VERSION 5.7 ;
  NOWIREEXTENSIONATPIN ON ;
  DIVIDERCHAR "/" ;
  BUSBITCHARS "[]" ;
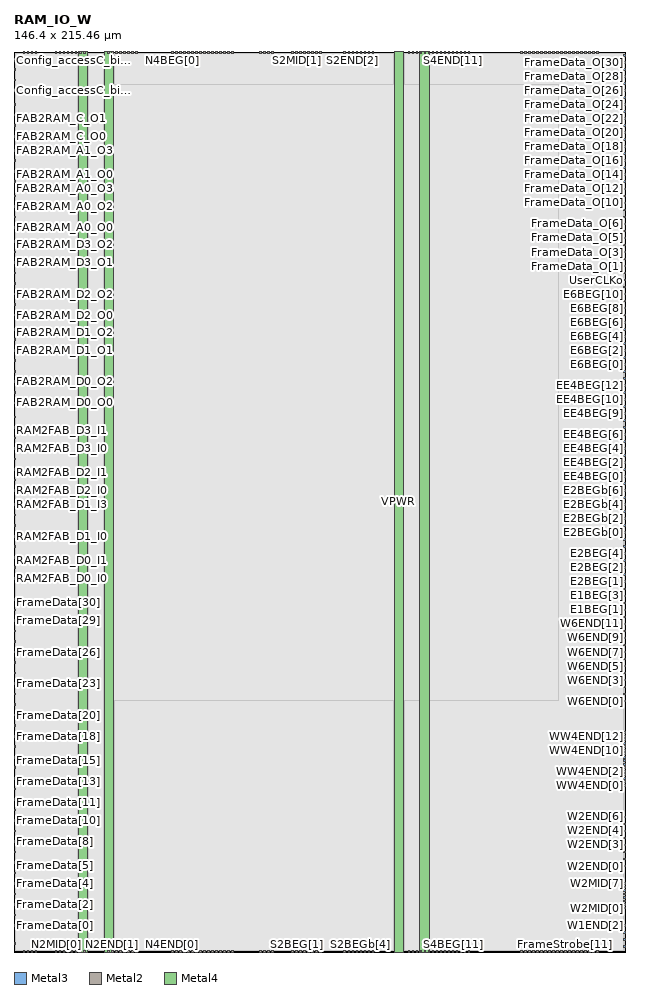
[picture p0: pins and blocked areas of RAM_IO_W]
MACRO RAM_IO_W
  CLASS BLOCK ;
  FOREIGN RAM_IO_W ;
  ORIGIN 0.000 0.000 ;
  SIZE 146.400 BY 215.460 ;
  PIN Config_accessC_bit0
    DIRECTION OUTPUT ;
    USE SIGNAL ;
    ANTENNADIFFAREA 2.647800 ;
    PORT
      LAYER Metal3 ;
        RECT 0.000 206.020 0.400 206.420 ;
    END
  END Config_accessC_bit0
  PIN Config_accessC_bit1
    DIRECTION OUTPUT ;
    USE SIGNAL ;
    ANTENNADIFFAREA 2.647800 ;
    PORT
      LAYER Metal3 ;
        RECT 0.000 208.540 0.400 208.940 ;
    END
  END Config_accessC_bit1
  PIN Config_accessC_bit2
    DIRECTION OUTPUT ;
    USE SIGNAL ;
    ANTENNADIFFAREA 2.647800 ;
    PORT
      LAYER Metal3 ;
        RECT 0.000 211.060 0.400 211.460 ;
    END
  END Config_accessC_bit2
  PIN Config_accessC_bit3
    DIRECTION OUTPUT ;
    USE SIGNAL ;
    ANTENNADIFFAREA 2.647800 ;
    PORT
      LAYER Metal3 ;
        RECT 0.000 213.580 0.400 213.980 ;
    END
  END Config_accessC_bit3
  PIN E1BEG[0]
    DIRECTION OUTPUT ;
    USE SIGNAL ;
    ANTENNADIFFAREA 2.724000 ;
    PORT
      LAYER Metal3 ;
        RECT 146.000 80.020 146.400 80.420 ;
    END
  END E1BEG[0]
  PIN E1BEG[1]
    DIRECTION OUTPUT ;
    USE SIGNAL ;
    ANTENNADIFFAREA 2.724000 ;
    PORT
      LAYER Metal3 ;
        RECT 146.000 81.700 146.400 82.100 ;
    END
  END E1BEG[1]
  PIN E1BEG[2]
    DIRECTION OUTPUT ;
    USE SIGNAL ;
    ANTENNADIFFAREA 2.724000 ;
    PORT
      LAYER Metal3 ;
        RECT 146.000 83.380 146.400 83.780 ;
    END
  END E1BEG[2]
  PIN E1BEG[3]
    DIRECTION OUTPUT ;
    USE SIGNAL ;
    ANTENNADIFFAREA 2.724000 ;
    PORT
      LAYER Metal3 ;
        RECT 146.000 85.060 146.400 85.460 ;
    END
  END E1BEG[3]
  PIN E2BEG[0]
    DIRECTION OUTPUT ;
    USE SIGNAL ;
    ANTENNADIFFAREA 2.724000 ;
    PORT
      LAYER Metal3 ;
        RECT 146.000 86.740 146.400 87.140 ;
    END
  END E2BEG[0]
  PIN E2BEG[1]
    DIRECTION OUTPUT ;
    USE SIGNAL ;
    ANTENNADIFFAREA 2.724000 ;
    PORT
      LAYER Metal3 ;
        RECT 146.000 88.420 146.400 88.820 ;
    END
  END E2BEG[1]
  PIN E2BEG[2]
    DIRECTION OUTPUT ;
    USE SIGNAL ;
    ANTENNADIFFAREA 2.724000 ;
    PORT
      LAYER Metal3 ;
        RECT 146.000 90.100 146.400 90.500 ;
    END
  END E2BEG[2]
  PIN E2BEG[3]
    DIRECTION OUTPUT ;
    USE SIGNAL ;
    ANTENNADIFFAREA 2.724000 ;
    PORT
      LAYER Metal3 ;
        RECT 146.000 91.780 146.400 92.180 ;
    END
  END E2BEG[3]
  PIN E2BEG[4]
    DIRECTION OUTPUT ;
    USE SIGNAL ;
    ANTENNADIFFAREA 2.724000 ;
    PORT
      LAYER Metal3 ;
        RECT 146.000 93.460 146.400 93.860 ;
    END
  END E2BEG[4]
  PIN E2BEG[5]
    DIRECTION OUTPUT ;
    USE SIGNAL ;
    ANTENNADIFFAREA 2.724000 ;
    PORT
      LAYER Metal3 ;
        RECT 146.000 95.140 146.400 95.540 ;
    END
  END E2BEG[5]
  PIN E2BEG[6]
    DIRECTION OUTPUT ;
    USE SIGNAL ;
    ANTENNADIFFAREA 2.724000 ;
    PORT
      LAYER Metal3 ;
        RECT 146.000 96.820 146.400 97.220 ;
    END
  END E2BEG[6]
  PIN E2BEG[7]
    DIRECTION OUTPUT ;
    USE SIGNAL ;
    ANTENNADIFFAREA 2.724000 ;
    PORT
      LAYER Metal3 ;
        RECT 146.000 98.500 146.400 98.900 ;
    END
  END E2BEG[7]
  PIN E2BEGb[0]
    DIRECTION OUTPUT ;
    USE SIGNAL ;
    ANTENNADIFFAREA 2.724000 ;
    PORT
      LAYER Metal3 ;
        RECT 146.000 100.180 146.400 100.580 ;
    END
  END E2BEGb[0]
  PIN E2BEGb[1]
    DIRECTION OUTPUT ;
    USE SIGNAL ;
    ANTENNADIFFAREA 2.724000 ;
    PORT
      LAYER Metal3 ;
        RECT 146.000 101.860 146.400 102.260 ;
    END
  END E2BEGb[1]
  PIN E2BEGb[2]
    DIRECTION OUTPUT ;
    USE SIGNAL ;
    ANTENNADIFFAREA 2.724000 ;
    PORT
      LAYER Metal3 ;
        RECT 146.000 103.540 146.400 103.940 ;
    END
  END E2BEGb[2]
  PIN E2BEGb[3]
    DIRECTION OUTPUT ;
    USE SIGNAL ;
    ANTENNADIFFAREA 2.724000 ;
    PORT
      LAYER Metal3 ;
        RECT 146.000 105.220 146.400 105.620 ;
    END
  END E2BEGb[3]
  PIN E2BEGb[4]
    DIRECTION OUTPUT ;
    USE SIGNAL ;
    ANTENNADIFFAREA 2.724000 ;
    PORT
      LAYER Metal3 ;
        RECT 146.000 106.900 146.400 107.300 ;
    END
  END E2BEGb[4]
  PIN E2BEGb[5]
    DIRECTION OUTPUT ;
    USE SIGNAL ;
    ANTENNADIFFAREA 2.724000 ;
    PORT
      LAYER Metal3 ;
        RECT 146.000 108.580 146.400 108.980 ;
    END
  END E2BEGb[5]
  PIN E2BEGb[6]
    DIRECTION OUTPUT ;
    USE SIGNAL ;
    ANTENNADIFFAREA 2.724000 ;
    PORT
      LAYER Metal3 ;
        RECT 146.000 110.260 146.400 110.660 ;
    END
  END E2BEGb[6]
  PIN E2BEGb[7]
    DIRECTION OUTPUT ;
    USE SIGNAL ;
    ANTENNADIFFAREA 2.724000 ;
    PORT
      LAYER Metal3 ;
        RECT 146.000 111.940 146.400 112.340 ;
    END
  END E2BEGb[7]
  PIN E6BEG[0]
    DIRECTION OUTPUT ;
    USE SIGNAL ;
    ANTENNADIFFAREA 2.724000 ;
    PORT
      LAYER Metal3 ;
        RECT 146.000 140.500 146.400 140.900 ;
    END
  END E6BEG[0]
  PIN E6BEG[10]
    DIRECTION OUTPUT ;
    USE SIGNAL ;
    ANTENNADIFFAREA 2.724000 ;
    PORT
      LAYER Metal3 ;
        RECT 146.000 157.300 146.400 157.700 ;
    END
  END E6BEG[10]
  PIN E6BEG[11]
    DIRECTION OUTPUT ;
    USE SIGNAL ;
    ANTENNADIFFAREA 2.724000 ;
    PORT
      LAYER Metal3 ;
        RECT 146.000 158.980 146.400 159.380 ;
    END
  END E6BEG[11]
  PIN E6BEG[1]
    DIRECTION OUTPUT ;
    USE SIGNAL ;
    ANTENNADIFFAREA 2.724000 ;
    PORT
      LAYER Metal3 ;
        RECT 146.000 142.180 146.400 142.580 ;
    END
  END E6BEG[1]
  PIN E6BEG[2]
    DIRECTION OUTPUT ;
    USE SIGNAL ;
    ANTENNADIFFAREA 2.724000 ;
    PORT
      LAYER Metal3 ;
        RECT 146.000 143.860 146.400 144.260 ;
    END
  END E6BEG[2]
  PIN E6BEG[3]
    DIRECTION OUTPUT ;
    USE SIGNAL ;
    ANTENNADIFFAREA 2.724000 ;
    PORT
      LAYER Metal3 ;
        RECT 146.000 145.540 146.400 145.940 ;
    END
  END E6BEG[3]
  PIN E6BEG[4]
    DIRECTION OUTPUT ;
    USE SIGNAL ;
    ANTENNADIFFAREA 2.724000 ;
    PORT
      LAYER Metal3 ;
        RECT 146.000 147.220 146.400 147.620 ;
    END
  END E6BEG[4]
  PIN E6BEG[5]
    DIRECTION OUTPUT ;
    USE SIGNAL ;
    ANTENNADIFFAREA 2.724000 ;
    PORT
      LAYER Metal3 ;
        RECT 146.000 148.900 146.400 149.300 ;
    END
  END E6BEG[5]
  PIN E6BEG[6]
    DIRECTION OUTPUT ;
    USE SIGNAL ;
    ANTENNADIFFAREA 2.724000 ;
    PORT
      LAYER Metal3 ;
        RECT 146.000 150.580 146.400 150.980 ;
    END
  END E6BEG[6]
  PIN E6BEG[7]
    DIRECTION OUTPUT ;
    USE SIGNAL ;
    ANTENNADIFFAREA 2.724000 ;
    PORT
      LAYER Metal3 ;
        RECT 146.000 152.260 146.400 152.660 ;
    END
  END E6BEG[7]
  PIN E6BEG[8]
    DIRECTION OUTPUT ;
    USE SIGNAL ;
    ANTENNADIFFAREA 2.724000 ;
    PORT
      LAYER Metal3 ;
        RECT 146.000 153.940 146.400 154.340 ;
    END
  END E6BEG[8]
  PIN E6BEG[9]
    DIRECTION OUTPUT ;
    USE SIGNAL ;
    ANTENNADIFFAREA 2.724000 ;
    PORT
      LAYER Metal3 ;
        RECT 146.000 155.620 146.400 156.020 ;
    END
  END E6BEG[9]
  PIN EE4BEG[0]
    DIRECTION OUTPUT ;
    USE SIGNAL ;
    ANTENNADIFFAREA 2.724000 ;
    PORT
      LAYER Metal3 ;
        RECT 146.000 113.620 146.400 114.020 ;
    END
  END EE4BEG[0]
  PIN EE4BEG[10]
    DIRECTION OUTPUT ;
    USE SIGNAL ;
    ANTENNADIFFAREA 2.724000 ;
    PORT
      LAYER Metal3 ;
        RECT 146.000 130.420 146.400 130.820 ;
    END
  END EE4BEG[10]
  PIN EE4BEG[11]
    DIRECTION OUTPUT ;
    USE SIGNAL ;
    ANTENNADIFFAREA 2.724000 ;
    PORT
      LAYER Metal3 ;
        RECT 146.000 132.100 146.400 132.500 ;
    END
  END EE4BEG[11]
  PIN EE4BEG[12]
    DIRECTION OUTPUT ;
    USE SIGNAL ;
    ANTENNADIFFAREA 2.724000 ;
    PORT
      LAYER Metal3 ;
        RECT 146.000 133.780 146.400 134.180 ;
    END
  END EE4BEG[12]
  PIN EE4BEG[13]
    DIRECTION OUTPUT ;
    USE SIGNAL ;
    ANTENNADIFFAREA 2.724000 ;
    PORT
      LAYER Metal3 ;
        RECT 146.000 135.460 146.400 135.860 ;
    END
  END EE4BEG[13]
  PIN EE4BEG[14]
    DIRECTION OUTPUT ;
    USE SIGNAL ;
    ANTENNADIFFAREA 2.724000 ;
    PORT
      LAYER Metal3 ;
        RECT 146.000 137.140 146.400 137.540 ;
    END
  END EE4BEG[14]
  PIN EE4BEG[15]
    DIRECTION OUTPUT ;
    USE SIGNAL ;
    ANTENNADIFFAREA 2.724000 ;
    PORT
      LAYER Metal3 ;
        RECT 146.000 138.820 146.400 139.220 ;
    END
  END EE4BEG[15]
  PIN EE4BEG[1]
    DIRECTION OUTPUT ;
    USE SIGNAL ;
    ANTENNADIFFAREA 2.724000 ;
    PORT
      LAYER Metal3 ;
        RECT 146.000 115.300 146.400 115.700 ;
    END
  END EE4BEG[1]
  PIN EE4BEG[2]
    DIRECTION OUTPUT ;
    USE SIGNAL ;
    ANTENNADIFFAREA 2.724000 ;
    PORT
      LAYER Metal3 ;
        RECT 146.000 116.980 146.400 117.380 ;
    END
  END EE4BEG[2]
  PIN EE4BEG[3]
    DIRECTION OUTPUT ;
    USE SIGNAL ;
    ANTENNADIFFAREA 2.724000 ;
    PORT
      LAYER Metal3 ;
        RECT 146.000 118.660 146.400 119.060 ;
    END
  END EE4BEG[3]
  PIN EE4BEG[4]
    DIRECTION OUTPUT ;
    USE SIGNAL ;
    ANTENNADIFFAREA 2.724000 ;
    PORT
      LAYER Metal3 ;
        RECT 146.000 120.340 146.400 120.740 ;
    END
  END EE4BEG[4]
  PIN EE4BEG[5]
    DIRECTION OUTPUT ;
    USE SIGNAL ;
    ANTENNADIFFAREA 2.724000 ;
    PORT
      LAYER Metal3 ;
        RECT 146.000 122.020 146.400 122.420 ;
    END
  END EE4BEG[5]
  PIN EE4BEG[6]
    DIRECTION OUTPUT ;
    USE SIGNAL ;
    ANTENNADIFFAREA 2.724000 ;
    PORT
      LAYER Metal3 ;
        RECT 146.000 123.700 146.400 124.100 ;
    END
  END EE4BEG[6]
  PIN EE4BEG[7]
    DIRECTION OUTPUT ;
    USE SIGNAL ;
    ANTENNADIFFAREA 2.724000 ;
    PORT
      LAYER Metal3 ;
        RECT 146.000 125.380 146.400 125.780 ;
    END
  END EE4BEG[7]
  PIN EE4BEG[8]
    DIRECTION OUTPUT ;
    USE SIGNAL ;
    ANTENNADIFFAREA 2.724000 ;
    PORT
      LAYER Metal3 ;
        RECT 146.000 127.060 146.400 127.460 ;
    END
  END EE4BEG[8]
  PIN EE4BEG[9]
    DIRECTION OUTPUT ;
    USE SIGNAL ;
    ANTENNADIFFAREA 2.724000 ;
    PORT
      LAYER Metal3 ;
        RECT 146.000 128.740 146.400 129.140 ;
    END
  END EE4BEG[9]
  PIN FAB2RAM_A0_O0
    DIRECTION OUTPUT ;
    USE SIGNAL ;
    ANTENNADIFFAREA 3.023500 ;
    PORT
      LAYER Metal3 ;
        RECT 0.000 173.260 0.400 173.660 ;
    END
  END FAB2RAM_A0_O0
  PIN FAB2RAM_A0_O1
    DIRECTION OUTPUT ;
    USE SIGNAL ;
    ANTENNADIFFAREA 3.023500 ;
    PORT
      LAYER Metal3 ;
        RECT 0.000 175.780 0.400 176.180 ;
    END
  END FAB2RAM_A0_O1
  PIN FAB2RAM_A0_O2
    DIRECTION OUTPUT ;
    USE SIGNAL ;
    ANTENNADIFFAREA 3.023500 ;
    PORT
      LAYER Metal3 ;
        RECT 0.000 178.300 0.400 178.700 ;
    END
  END FAB2RAM_A0_O2
  PIN FAB2RAM_A0_O3
    DIRECTION OUTPUT ;
    USE SIGNAL ;
    ANTENNADIFFAREA 3.023500 ;
    PORT
      LAYER Metal3 ;
        RECT 0.000 180.820 0.400 181.220 ;
    END
  END FAB2RAM_A0_O3
  PIN FAB2RAM_A1_O0
    DIRECTION OUTPUT ;
    USE SIGNAL ;
    ANTENNADIFFAREA 3.023500 ;
    PORT
      LAYER Metal3 ;
        RECT 0.000 184.180 0.400 184.580 ;
    END
  END FAB2RAM_A1_O0
  PIN FAB2RAM_A1_O1
    DIRECTION OUTPUT ;
    USE SIGNAL ;
    ANTENNADIFFAREA 3.023500 ;
    PORT
      LAYER Metal3 ;
        RECT 0.000 186.700 0.400 187.100 ;
    END
  END FAB2RAM_A1_O1
  PIN FAB2RAM_A1_O2
    DIRECTION OUTPUT ;
    USE SIGNAL ;
    ANTENNADIFFAREA 3.023500 ;
    PORT
      LAYER Metal3 ;
        RECT 0.000 189.220 0.400 189.620 ;
    END
  END FAB2RAM_A1_O2
  PIN FAB2RAM_A1_O3
    DIRECTION OUTPUT ;
    USE SIGNAL ;
    ANTENNADIFFAREA 3.023500 ;
    PORT
      LAYER Metal3 ;
        RECT 0.000 191.740 0.400 192.140 ;
    END
  END FAB2RAM_A1_O3
  PIN FAB2RAM_C_O0
    DIRECTION OUTPUT ;
    USE SIGNAL ;
    ANTENNADIFFAREA 3.023500 ;
    PORT
      LAYER Metal3 ;
        RECT 0.000 195.100 0.400 195.500 ;
    END
  END FAB2RAM_C_O0
  PIN FAB2RAM_C_O1
    DIRECTION OUTPUT ;
    USE SIGNAL ;
    ANTENNADIFFAREA 3.023500 ;
    PORT
      LAYER Metal3 ;
        RECT 0.000 197.620 0.400 198.020 ;
    END
  END FAB2RAM_C_O1
  PIN FAB2RAM_C_O2
    DIRECTION OUTPUT ;
    USE SIGNAL ;
    ANTENNADIFFAREA 3.023500 ;
    PORT
      LAYER Metal3 ;
        RECT 0.000 200.140 0.400 200.540 ;
    END
  END FAB2RAM_C_O2
  PIN FAB2RAM_C_O3
    DIRECTION OUTPUT ;
    USE SIGNAL ;
    ANTENNADIFFAREA 3.023500 ;
    PORT
      LAYER Metal3 ;
        RECT 0.000 202.660 0.400 203.060 ;
    END
  END FAB2RAM_C_O3
  PIN FAB2RAM_D0_O0
    DIRECTION OUTPUT ;
    USE SIGNAL ;
    ANTENNADIFFAREA 3.023500 ;
    PORT
      LAYER Metal3 ;
        RECT 0.000 131.260 0.400 131.660 ;
    END
  END FAB2RAM_D0_O0
  PIN FAB2RAM_D0_O1
    DIRECTION OUTPUT ;
    USE SIGNAL ;
    ANTENNADIFFAREA 3.023500 ;
    PORT
      LAYER Metal3 ;
        RECT 0.000 133.780 0.400 134.180 ;
    END
  END FAB2RAM_D0_O1
  PIN FAB2RAM_D0_O2
    DIRECTION OUTPUT ;
    USE SIGNAL ;
    ANTENNADIFFAREA 3.023500 ;
    PORT
      LAYER Metal3 ;
        RECT 0.000 136.300 0.400 136.700 ;
    END
  END FAB2RAM_D0_O2
  PIN FAB2RAM_D0_O3
    DIRECTION OUTPUT ;
    USE SIGNAL ;
    ANTENNADIFFAREA 3.023500 ;
    PORT
      LAYER Metal3 ;
        RECT 0.000 138.820 0.400 139.220 ;
    END
  END FAB2RAM_D0_O3
  PIN FAB2RAM_D1_O0
    DIRECTION OUTPUT ;
    USE SIGNAL ;
    ANTENNADIFFAREA 3.023500 ;
    PORT
      LAYER Metal3 ;
        RECT 0.000 141.340 0.400 141.740 ;
    END
  END FAB2RAM_D1_O0
  PIN FAB2RAM_D1_O1
    DIRECTION OUTPUT ;
    USE SIGNAL ;
    ANTENNADIFFAREA 3.023500 ;
    PORT
      LAYER Metal3 ;
        RECT 0.000 143.860 0.400 144.260 ;
    END
  END FAB2RAM_D1_O1
  PIN FAB2RAM_D1_O2
    DIRECTION OUTPUT ;
    USE SIGNAL ;
    ANTENNADIFFAREA 3.023500 ;
    PORT
      LAYER Metal3 ;
        RECT 0.000 146.380 0.400 146.780 ;
    END
  END FAB2RAM_D1_O2
  PIN FAB2RAM_D1_O3
    DIRECTION OUTPUT ;
    USE SIGNAL ;
    ANTENNADIFFAREA 3.023500 ;
    PORT
      LAYER Metal3 ;
        RECT 0.000 148.900 0.400 149.300 ;
    END
  END FAB2RAM_D1_O3
  PIN FAB2RAM_D2_O0
    DIRECTION OUTPUT ;
    USE SIGNAL ;
    ANTENNADIFFAREA 3.023500 ;
    PORT
      LAYER Metal3 ;
        RECT 0.000 152.260 0.400 152.660 ;
    END
  END FAB2RAM_D2_O0
  PIN FAB2RAM_D2_O1
    DIRECTION OUTPUT ;
    USE SIGNAL ;
    ANTENNADIFFAREA 3.023500 ;
    PORT
      LAYER Metal3 ;
        RECT 0.000 154.780 0.400 155.180 ;
    END
  END FAB2RAM_D2_O1
  PIN FAB2RAM_D2_O2
    DIRECTION OUTPUT ;
    USE SIGNAL ;
    ANTENNADIFFAREA 3.023500 ;
    PORT
      LAYER Metal3 ;
        RECT 0.000 157.300 0.400 157.700 ;
    END
  END FAB2RAM_D2_O2
  PIN FAB2RAM_D2_O3
    DIRECTION OUTPUT ;
    USE SIGNAL ;
    ANTENNADIFFAREA 3.023500 ;
    PORT
      LAYER Metal3 ;
        RECT 0.000 159.820 0.400 160.220 ;
    END
  END FAB2RAM_D2_O3
  PIN FAB2RAM_D3_O0
    DIRECTION OUTPUT ;
    USE SIGNAL ;
    ANTENNADIFFAREA 3.023500 ;
    PORT
      LAYER Metal3 ;
        RECT 0.000 162.340 0.400 162.740 ;
    END
  END FAB2RAM_D3_O0
  PIN FAB2RAM_D3_O1
    DIRECTION OUTPUT ;
    USE SIGNAL ;
    ANTENNADIFFAREA 3.023500 ;
    PORT
      LAYER Metal3 ;
        RECT 0.000 164.860 0.400 165.260 ;
    END
  END FAB2RAM_D3_O1
  PIN FAB2RAM_D3_O2
    DIRECTION OUTPUT ;
    USE SIGNAL ;
    ANTENNADIFFAREA 3.023500 ;
    PORT
      LAYER Metal3 ;
        RECT 0.000 167.380 0.400 167.780 ;
    END
  END FAB2RAM_D3_O2
  PIN FAB2RAM_D3_O3
    DIRECTION OUTPUT ;
    USE SIGNAL ;
    ANTENNADIFFAREA 3.023500 ;
    PORT
      LAYER Metal3 ;
        RECT 0.000 169.900 0.400 170.300 ;
    END
  END FAB2RAM_D3_O3
  PIN FrameData[0]
    DIRECTION INPUT ;
    USE SIGNAL ;
    ANTENNAGATEAREA 1.987700 ;
    ANTENNADIFFAREA 22.169399 ;
    PORT
      LAYER Metal3 ;
        RECT 0.000 6.100 0.400 6.500 ;
    END
  END FrameData[0]
  PIN FrameData[10]
    DIRECTION INPUT ;
    USE SIGNAL ;
    ANTENNAGATEAREA 1.987700 ;
    ANTENNADIFFAREA 22.169399 ;
    PORT
      LAYER Metal3 ;
        RECT 0.000 31.300 0.400 31.700 ;
    END
  END FrameData[10]
  PIN FrameData[11]
    DIRECTION INPUT ;
    USE SIGNAL ;
    ANTENNAGATEAREA 1.987700 ;
    ANTENNADIFFAREA 22.169399 ;
    PORT
      LAYER Metal3 ;
        RECT 0.000 33.820 0.400 34.220 ;
    END
  END FrameData[11]
  PIN FrameData[12]
    DIRECTION INPUT ;
    USE SIGNAL ;
    ANTENNAGATEAREA 1.987700 ;
    ANTENNADIFFAREA 22.169399 ;
    PORT
      LAYER Metal3 ;
        RECT 0.000 36.340 0.400 36.740 ;
    END
  END FrameData[12]
  PIN FrameData[13]
    DIRECTION INPUT ;
    USE SIGNAL ;
    ANTENNAGATEAREA 1.987700 ;
    ANTENNADIFFAREA 22.169399 ;
    PORT
      LAYER Metal3 ;
        RECT 0.000 38.860 0.400 39.260 ;
    END
  END FrameData[13]
  PIN FrameData[14]
    DIRECTION INPUT ;
    USE SIGNAL ;
    ANTENNAGATEAREA 1.987700 ;
    ANTENNADIFFAREA 22.169399 ;
    PORT
      LAYER Metal3 ;
        RECT 0.000 41.380 0.400 41.780 ;
    END
  END FrameData[14]
  PIN FrameData[15]
    DIRECTION INPUT ;
    USE SIGNAL ;
    ANTENNAGATEAREA 1.987700 ;
    ANTENNADIFFAREA 22.169399 ;
    PORT
      LAYER Metal3 ;
        RECT 0.000 43.900 0.400 44.300 ;
    END
  END FrameData[15]
  PIN FrameData[16]
    DIRECTION INPUT ;
    USE SIGNAL ;
    ANTENNAGATEAREA 1.987700 ;
    ANTENNADIFFAREA 22.169399 ;
    PORT
      LAYER Metal3 ;
        RECT 0.000 46.420 0.400 46.820 ;
    END
  END FrameData[16]
  PIN FrameData[17]
    DIRECTION INPUT ;
    USE SIGNAL ;
    ANTENNAGATEAREA 1.987700 ;
    ANTENNADIFFAREA 22.169399 ;
    PORT
      LAYER Metal3 ;
        RECT 0.000 48.940 0.400 49.340 ;
    END
  END FrameData[17]
  PIN FrameData[18]
    DIRECTION INPUT ;
    USE SIGNAL ;
    ANTENNAGATEAREA 1.987700 ;
    ANTENNADIFFAREA 22.169399 ;
    PORT
      LAYER Metal3 ;
        RECT 0.000 51.460 0.400 51.860 ;
    END
  END FrameData[18]
  PIN FrameData[19]
    DIRECTION INPUT ;
    USE SIGNAL ;
    ANTENNAGATEAREA 1.987700 ;
    ANTENNADIFFAREA 22.169399 ;
    PORT
      LAYER Metal3 ;
        RECT 0.000 53.980 0.400 54.380 ;
    END
  END FrameData[19]
  PIN FrameData[1]
    DIRECTION INPUT ;
    USE SIGNAL ;
    ANTENNAGATEAREA 1.987700 ;
    ANTENNADIFFAREA 22.169399 ;
    PORT
      LAYER Metal3 ;
        RECT 0.000 8.620 0.400 9.020 ;
    END
  END FrameData[1]
  PIN FrameData[20]
    DIRECTION INPUT ;
    USE SIGNAL ;
    ANTENNAGATEAREA 1.987700 ;
    ANTENNADIFFAREA 22.169399 ;
    PORT
      LAYER Metal3 ;
        RECT 0.000 56.500 0.400 56.900 ;
    END
  END FrameData[20]
  PIN FrameData[21]
    DIRECTION INPUT ;
    USE SIGNAL ;
    ANTENNAGATEAREA 1.987700 ;
    ANTENNADIFFAREA 22.169399 ;
    PORT
      LAYER Metal3 ;
        RECT 0.000 59.020 0.400 59.420 ;
    END
  END FrameData[21]
  PIN FrameData[22]
    DIRECTION INPUT ;
    USE SIGNAL ;
    ANTENNAGATEAREA 1.987700 ;
    ANTENNADIFFAREA 22.169399 ;
    PORT
      LAYER Metal3 ;
        RECT 0.000 61.540 0.400 61.940 ;
    END
  END FrameData[22]
  PIN FrameData[23]
    DIRECTION INPUT ;
    USE SIGNAL ;
    ANTENNAGATEAREA 1.987700 ;
    ANTENNADIFFAREA 22.169399 ;
    PORT
      LAYER Metal3 ;
        RECT 0.000 64.060 0.400 64.460 ;
    END
  END FrameData[23]
  PIN FrameData[24]
    DIRECTION INPUT ;
    USE SIGNAL ;
    ANTENNAGATEAREA 2.168400 ;
    ANTENNADIFFAREA 24.184799 ;
    PORT
      LAYER Metal3 ;
        RECT 0.000 66.580 0.400 66.980 ;
    END
  END FrameData[24]
  PIN FrameData[25]
    DIRECTION INPUT ;
    USE SIGNAL ;
    ANTENNAGATEAREA 2.168400 ;
    ANTENNADIFFAREA 24.184799 ;
    PORT
      LAYER Metal3 ;
        RECT 0.000 69.100 0.400 69.500 ;
    END
  END FrameData[25]
  PIN FrameData[26]
    DIRECTION INPUT ;
    USE SIGNAL ;
    ANTENNAGATEAREA 2.168400 ;
    ANTENNADIFFAREA 24.184799 ;
    PORT
      LAYER Metal3 ;
        RECT 0.000 71.620 0.400 72.020 ;
    END
  END FrameData[26]
  PIN FrameData[27]
    DIRECTION INPUT ;
    USE SIGNAL ;
    ANTENNAGATEAREA 2.168400 ;
    ANTENNADIFFAREA 24.184799 ;
    PORT
      LAYER Metal3 ;
        RECT 0.000 74.140 0.400 74.540 ;
    END
  END FrameData[27]
  PIN FrameData[28]
    DIRECTION INPUT ;
    USE SIGNAL ;
    ANTENNAGATEAREA 2.168400 ;
    ANTENNADIFFAREA 24.184799 ;
    PORT
      LAYER Metal3 ;
        RECT 0.000 76.660 0.400 77.060 ;
    END
  END FrameData[28]
  PIN FrameData[29]
    DIRECTION INPUT ;
    USE SIGNAL ;
    ANTENNAGATEAREA 2.168400 ;
    ANTENNADIFFAREA 24.184799 ;
    PORT
      LAYER Metal3 ;
        RECT 0.000 79.180 0.400 79.580 ;
    END
  END FrameData[29]
  PIN FrameData[2]
    DIRECTION INPUT ;
    USE SIGNAL ;
    ANTENNAGATEAREA 1.987700 ;
    ANTENNADIFFAREA 22.169399 ;
    PORT
      LAYER Metal3 ;
        RECT 0.000 11.140 0.400 11.540 ;
    END
  END FrameData[2]
  PIN FrameData[30]
    DIRECTION INPUT ;
    USE SIGNAL ;
    ANTENNAGATEAREA 2.168400 ;
    ANTENNADIFFAREA 24.184799 ;
    PORT
      LAYER Metal3 ;
        RECT 0.000 81.700 0.400 82.100 ;
    END
  END FrameData[30]
  PIN FrameData[31]
    DIRECTION INPUT ;
    USE SIGNAL ;
    ANTENNAGATEAREA 2.168400 ;
    ANTENNADIFFAREA 24.184799 ;
    PORT
      LAYER Metal3 ;
        RECT 0.000 84.220 0.400 84.620 ;
    END
  END FrameData[31]
  PIN FrameData[3]
    DIRECTION INPUT ;
    USE SIGNAL ;
    ANTENNAGATEAREA 1.987700 ;
    ANTENNADIFFAREA 22.169399 ;
    PORT
      LAYER Metal3 ;
        RECT 0.000 13.660 0.400 14.060 ;
    END
  END FrameData[3]
  PIN FrameData[4]
    DIRECTION INPUT ;
    USE SIGNAL ;
    ANTENNAGATEAREA 1.987700 ;
    ANTENNADIFFAREA 22.169399 ;
    PORT
      LAYER Metal3 ;
        RECT 0.000 16.180 0.400 16.580 ;
    END
  END FrameData[4]
  PIN FrameData[5]
    DIRECTION INPUT ;
    USE SIGNAL ;
    ANTENNAGATEAREA 1.987700 ;
    ANTENNADIFFAREA 22.169399 ;
    PORT
      LAYER Metal3 ;
        RECT 0.000 18.700 0.400 19.100 ;
    END
  END FrameData[5]
  PIN FrameData[6]
    DIRECTION INPUT ;
    USE SIGNAL ;
    ANTENNAGATEAREA 1.987700 ;
    ANTENNADIFFAREA 22.169399 ;
    PORT
      LAYER Metal3 ;
        RECT 0.000 21.220 0.400 21.620 ;
    END
  END FrameData[6]
  PIN FrameData[7]
    DIRECTION INPUT ;
    USE SIGNAL ;
    ANTENNAGATEAREA 1.987700 ;
    ANTENNADIFFAREA 22.169399 ;
    PORT
      LAYER Metal3 ;
        RECT 0.000 23.740 0.400 24.140 ;
    END
  END FrameData[7]
  PIN FrameData[8]
    DIRECTION INPUT ;
    USE SIGNAL ;
    ANTENNAGATEAREA 1.987700 ;
    ANTENNADIFFAREA 22.169399 ;
    PORT
      LAYER Metal3 ;
        RECT 0.000 26.260 0.400 26.660 ;
    END
  END FrameData[8]
  PIN FrameData[9]
    DIRECTION INPUT ;
    USE SIGNAL ;
    ANTENNAGATEAREA 1.987700 ;
    ANTENNADIFFAREA 22.169399 ;
    PORT
      LAYER Metal3 ;
        RECT 0.000 28.780 0.400 29.180 ;
    END
  END FrameData[9]
  PIN FrameData_O[0]
    DIRECTION OUTPUT ;
    USE SIGNAL ;
    ANTENNADIFFAREA 2.724000 ;
    PORT
      LAYER Metal3 ;
        RECT 146.000 162.340 146.400 162.740 ;
    END
  END FrameData_O[0]
  PIN FrameData_O[10]
    DIRECTION OUTPUT ;
    USE SIGNAL ;
    ANTENNADIFFAREA 2.724000 ;
    PORT
      LAYER Metal3 ;
        RECT 146.000 179.140 146.400 179.540 ;
    END
  END FrameData_O[10]
  PIN FrameData_O[11]
    DIRECTION OUTPUT ;
    USE SIGNAL ;
    ANTENNADIFFAREA 2.724000 ;
    PORT
      LAYER Metal3 ;
        RECT 146.000 180.820 146.400 181.220 ;
    END
  END FrameData_O[11]
  PIN FrameData_O[12]
    DIRECTION OUTPUT ;
    USE SIGNAL ;
    ANTENNADIFFAREA 2.724000 ;
    PORT
      LAYER Metal3 ;
        RECT 146.000 182.500 146.400 182.900 ;
    END
  END FrameData_O[12]
  PIN FrameData_O[13]
    DIRECTION OUTPUT ;
    USE SIGNAL ;
    ANTENNADIFFAREA 2.724000 ;
    PORT
      LAYER Metal3 ;
        RECT 146.000 184.180 146.400 184.580 ;
    END
  END FrameData_O[13]
  PIN FrameData_O[14]
    DIRECTION OUTPUT ;
    USE SIGNAL ;
    ANTENNADIFFAREA 2.724000 ;
    PORT
      LAYER Metal3 ;
        RECT 146.000 185.860 146.400 186.260 ;
    END
  END FrameData_O[14]
  PIN FrameData_O[15]
    DIRECTION OUTPUT ;
    USE SIGNAL ;
    ANTENNADIFFAREA 2.724000 ;
    PORT
      LAYER Metal3 ;
        RECT 146.000 187.540 146.400 187.940 ;
    END
  END FrameData_O[15]
  PIN FrameData_O[16]
    DIRECTION OUTPUT ;
    USE SIGNAL ;
    ANTENNADIFFAREA 2.724000 ;
    PORT
      LAYER Metal3 ;
        RECT 146.000 189.220 146.400 189.620 ;
    END
  END FrameData_O[16]
  PIN FrameData_O[17]
    DIRECTION OUTPUT ;
    USE SIGNAL ;
    ANTENNADIFFAREA 2.724000 ;
    PORT
      LAYER Metal3 ;
        RECT 146.000 190.900 146.400 191.300 ;
    END
  END FrameData_O[17]
  PIN FrameData_O[18]
    DIRECTION OUTPUT ;
    USE SIGNAL ;
    ANTENNADIFFAREA 2.724000 ;
    PORT
      LAYER Metal3 ;
        RECT 146.000 192.580 146.400 192.980 ;
    END
  END FrameData_O[18]
  PIN FrameData_O[19]
    DIRECTION OUTPUT ;
    USE SIGNAL ;
    ANTENNADIFFAREA 2.724000 ;
    PORT
      LAYER Metal3 ;
        RECT 146.000 194.260 146.400 194.660 ;
    END
  END FrameData_O[19]
  PIN FrameData_O[1]
    DIRECTION OUTPUT ;
    USE SIGNAL ;
    ANTENNADIFFAREA 2.724000 ;
    PORT
      LAYER Metal3 ;
        RECT 146.000 164.020 146.400 164.420 ;
    END
  END FrameData_O[1]
  PIN FrameData_O[20]
    DIRECTION OUTPUT ;
    USE SIGNAL ;
    ANTENNADIFFAREA 2.724000 ;
    PORT
      LAYER Metal3 ;
        RECT 146.000 195.940 146.400 196.340 ;
    END
  END FrameData_O[20]
  PIN FrameData_O[21]
    DIRECTION OUTPUT ;
    USE SIGNAL ;
    ANTENNADIFFAREA 2.724000 ;
    PORT
      LAYER Metal3 ;
        RECT 146.000 197.620 146.400 198.020 ;
    END
  END FrameData_O[21]
  PIN FrameData_O[22]
    DIRECTION OUTPUT ;
    USE SIGNAL ;
    ANTENNADIFFAREA 2.724000 ;
    PORT
      LAYER Metal3 ;
        RECT 146.000 199.300 146.400 199.700 ;
    END
  END FrameData_O[22]
  PIN FrameData_O[23]
    DIRECTION OUTPUT ;
    USE SIGNAL ;
    ANTENNADIFFAREA 2.724000 ;
    PORT
      LAYER Metal3 ;
        RECT 146.000 200.980 146.400 201.380 ;
    END
  END FrameData_O[23]
  PIN FrameData_O[24]
    DIRECTION OUTPUT ;
    USE SIGNAL ;
    ANTENNADIFFAREA 2.724000 ;
    PORT
      LAYER Metal3 ;
        RECT 146.000 202.660 146.400 203.060 ;
    END
  END FrameData_O[24]
  PIN FrameData_O[25]
    DIRECTION OUTPUT ;
    USE SIGNAL ;
    ANTENNADIFFAREA 2.724000 ;
    PORT
      LAYER Metal3 ;
        RECT 146.000 204.340 146.400 204.740 ;
    END
  END FrameData_O[25]
  PIN FrameData_O[26]
    DIRECTION OUTPUT ;
    USE SIGNAL ;
    ANTENNADIFFAREA 2.724000 ;
    PORT
      LAYER Metal3 ;
        RECT 146.000 206.020 146.400 206.420 ;
    END
  END FrameData_O[26]
  PIN FrameData_O[27]
    DIRECTION OUTPUT ;
    USE SIGNAL ;
    ANTENNADIFFAREA 2.724000 ;
    PORT
      LAYER Metal3 ;
        RECT 146.000 207.700 146.400 208.100 ;
    END
  END FrameData_O[27]
  PIN FrameData_O[28]
    DIRECTION OUTPUT ;
    USE SIGNAL ;
    ANTENNADIFFAREA 2.724000 ;
    PORT
      LAYER Metal3 ;
        RECT 146.000 209.380 146.400 209.780 ;
    END
  END FrameData_O[28]
  PIN FrameData_O[29]
    DIRECTION OUTPUT ;
    USE SIGNAL ;
    ANTENNADIFFAREA 2.724000 ;
    PORT
      LAYER Metal3 ;
        RECT 146.000 211.060 146.400 211.460 ;
    END
  END FrameData_O[29]
  PIN FrameData_O[2]
    DIRECTION OUTPUT ;
    USE SIGNAL ;
    ANTENNADIFFAREA 2.724000 ;
    PORT
      LAYER Metal3 ;
        RECT 146.000 165.700 146.400 166.100 ;
    END
  END FrameData_O[2]
  PIN FrameData_O[30]
    DIRECTION OUTPUT ;
    USE SIGNAL ;
    ANTENNADIFFAREA 2.724000 ;
    PORT
      LAYER Metal3 ;
        RECT 146.000 212.740 146.400 213.140 ;
    END
  END FrameData_O[30]
  PIN FrameData_O[31]
    DIRECTION OUTPUT ;
    USE SIGNAL ;
    ANTENNADIFFAREA 2.724000 ;
    PORT
      LAYER Metal3 ;
        RECT 146.000 214.420 146.400 214.820 ;
    END
  END FrameData_O[31]
  PIN FrameData_O[3]
    DIRECTION OUTPUT ;
    USE SIGNAL ;
    ANTENNADIFFAREA 2.724000 ;
    PORT
      LAYER Metal3 ;
        RECT 146.000 167.380 146.400 167.780 ;
    END
  END FrameData_O[3]
  PIN FrameData_O[4]
    DIRECTION OUTPUT ;
    USE SIGNAL ;
    ANTENNADIFFAREA 2.724000 ;
    PORT
      LAYER Metal3 ;
        RECT 146.000 169.060 146.400 169.460 ;
    END
  END FrameData_O[4]
  PIN FrameData_O[5]
    DIRECTION OUTPUT ;
    USE SIGNAL ;
    ANTENNADIFFAREA 2.724000 ;
    PORT
      LAYER Metal3 ;
        RECT 146.000 170.740 146.400 171.140 ;
    END
  END FrameData_O[5]
  PIN FrameData_O[6]
    DIRECTION OUTPUT ;
    USE SIGNAL ;
    ANTENNADIFFAREA 2.724000 ;
    PORT
      LAYER Metal3 ;
        RECT 146.000 172.420 146.400 172.820 ;
    END
  END FrameData_O[6]
  PIN FrameData_O[7]
    DIRECTION OUTPUT ;
    USE SIGNAL ;
    ANTENNADIFFAREA 2.724000 ;
    PORT
      LAYER Metal3 ;
        RECT 146.000 174.100 146.400 174.500 ;
    END
  END FrameData_O[7]
  PIN FrameData_O[8]
    DIRECTION OUTPUT ;
    USE SIGNAL ;
    ANTENNADIFFAREA 2.724000 ;
    PORT
      LAYER Metal3 ;
        RECT 146.000 175.780 146.400 176.180 ;
    END
  END FrameData_O[8]
  PIN FrameData_O[9]
    DIRECTION OUTPUT ;
    USE SIGNAL ;
    ANTENNADIFFAREA 2.724000 ;
    PORT
      LAYER Metal3 ;
        RECT 146.000 177.460 146.400 177.860 ;
    END
  END FrameData_O[9]
  PIN FrameStrobe[0]
    DIRECTION INPUT ;
    USE SIGNAL ;
    ANTENNAGATEAREA 6.753500 ;
    ANTENNADIFFAREA 66.508202 ;
    PORT
      LAYER Metal2 ;
        RECT 121.240 0.000 121.640 0.400 ;
    END
  END FrameStrobe[0]
  PIN FrameStrobe[10]
    DIRECTION INPUT ;
    USE SIGNAL ;
    ANTENNAGATEAREA 1.823900 ;
    ANTENNADIFFAREA 18.138599 ;
    PORT
      LAYER Metal2 ;
        RECT 130.840 0.000 131.240 0.400 ;
    END
  END FrameStrobe[10]
  PIN FrameStrobe[11]
    DIRECTION INPUT ;
    USE SIGNAL ;
    ANTENNAGATEAREA 0.180700 ;
    ANTENNADIFFAREA 2.015400 ;
    PORT
      LAYER Metal2 ;
        RECT 131.800 0.000 132.200 0.400 ;
    END
  END FrameStrobe[11]
  PIN FrameStrobe[12]
    DIRECTION INPUT ;
    USE SIGNAL ;
    ANTENNAGATEAREA 0.180700 ;
    ANTENNADIFFAREA 2.015400 ;
    PORT
      LAYER Metal2 ;
        RECT 132.760 0.000 133.160 0.400 ;
    END
  END FrameStrobe[12]
  PIN FrameStrobe[13]
    DIRECTION INPUT ;
    USE SIGNAL ;
    ANTENNAGATEAREA 0.180700 ;
    ANTENNADIFFAREA 2.015400 ;
    PORT
      LAYER Metal2 ;
        RECT 133.720 0.000 134.120 0.400 ;
    END
  END FrameStrobe[13]
  PIN FrameStrobe[14]
    DIRECTION INPUT ;
    USE SIGNAL ;
    ANTENNAGATEAREA 0.180700 ;
    ANTENNADIFFAREA 2.015400 ;
    PORT
      LAYER Metal2 ;
        RECT 134.680 0.000 135.080 0.400 ;
    END
  END FrameStrobe[14]
  PIN FrameStrobe[15]
    DIRECTION INPUT ;
    USE SIGNAL ;
    ANTENNAGATEAREA 0.180700 ;
    ANTENNADIFFAREA 2.015400 ;
    PORT
      LAYER Metal2 ;
        RECT 135.640 0.000 136.040 0.400 ;
    END
  END FrameStrobe[15]
  PIN FrameStrobe[16]
    DIRECTION INPUT ;
    USE SIGNAL ;
    ANTENNAGATEAREA 0.180700 ;
    ANTENNADIFFAREA 2.015400 ;
    PORT
      LAYER Metal2 ;
        RECT 136.600 0.000 137.000 0.400 ;
    END
  END FrameStrobe[16]
  PIN FrameStrobe[17]
    DIRECTION INPUT ;
    USE SIGNAL ;
    ANTENNAGATEAREA 0.180700 ;
    ANTENNADIFFAREA 2.015400 ;
    PORT
      LAYER Metal2 ;
        RECT 137.560 0.000 137.960 0.400 ;
    END
  END FrameStrobe[17]
  PIN FrameStrobe[18]
    DIRECTION INPUT ;
    USE SIGNAL ;
    ANTENNAGATEAREA 0.180700 ;
    ANTENNADIFFAREA 2.015400 ;
    PORT
      LAYER Metal2 ;
        RECT 138.520 0.000 138.920 0.400 ;
    END
  END FrameStrobe[18]
  PIN FrameStrobe[19]
    DIRECTION INPUT ;
    USE SIGNAL ;
    ANTENNAGATEAREA 0.180700 ;
    ANTENNADIFFAREA 2.015400 ;
    PORT
      LAYER Metal2 ;
        RECT 139.480 0.000 139.880 0.400 ;
    END
  END FrameStrobe[19]
  PIN FrameStrobe[1]
    DIRECTION INPUT ;
    USE SIGNAL ;
    ANTENNAGATEAREA 6.753500 ;
    ANTENNADIFFAREA 66.508202 ;
    PORT
      LAYER Metal2 ;
        RECT 122.200 0.000 122.600 0.400 ;
    END
  END FrameStrobe[1]
  PIN FrameStrobe[2]
    DIRECTION INPUT ;
    USE SIGNAL ;
    ANTENNAGATEAREA 6.753500 ;
    ANTENNADIFFAREA 66.508202 ;
    PORT
      LAYER Metal2 ;
        RECT 123.160 0.000 123.560 0.400 ;
    END
  END FrameStrobe[2]
  PIN FrameStrobe[3]
    DIRECTION INPUT ;
    USE SIGNAL ;
    ANTENNAGATEAREA 6.753500 ;
    ANTENNADIFFAREA 66.508202 ;
    PORT
      LAYER Metal2 ;
        RECT 124.120 0.000 124.520 0.400 ;
    END
  END FrameStrobe[3]
  PIN FrameStrobe[4]
    DIRECTION INPUT ;
    USE SIGNAL ;
    ANTENNAGATEAREA 6.753500 ;
    ANTENNADIFFAREA 66.508202 ;
    PORT
      LAYER Metal2 ;
        RECT 125.080 0.000 125.480 0.400 ;
    END
  END FrameStrobe[4]
  PIN FrameStrobe[5]
    DIRECTION INPUT ;
    USE SIGNAL ;
    ANTENNAGATEAREA 6.753500 ;
    ANTENNADIFFAREA 66.508202 ;
    PORT
      LAYER Metal2 ;
        RECT 126.040 0.000 126.440 0.400 ;
    END
  END FrameStrobe[5]
  PIN FrameStrobe[6]
    DIRECTION INPUT ;
    USE SIGNAL ;
    ANTENNAGATEAREA 6.753500 ;
    ANTENNADIFFAREA 66.508202 ;
    PORT
      LAYER Metal2 ;
        RECT 127.000 0.000 127.400 0.400 ;
    END
  END FrameStrobe[6]
  PIN FrameStrobe[7]
    DIRECTION INPUT ;
    USE SIGNAL ;
    ANTENNAGATEAREA 6.753500 ;
    ANTENNADIFFAREA 66.508202 ;
    PORT
      LAYER Metal2 ;
        RECT 127.960 0.000 128.360 0.400 ;
    END
  END FrameStrobe[7]
  PIN FrameStrobe[8]
    DIRECTION INPUT ;
    USE SIGNAL ;
    ANTENNAGATEAREA 6.753500 ;
    ANTENNADIFFAREA 66.508202 ;
    PORT
      LAYER Metal2 ;
        RECT 128.920 0.000 129.320 0.400 ;
    END
  END FrameStrobe[8]
  PIN FrameStrobe[9]
    DIRECTION INPUT ;
    USE SIGNAL ;
    ANTENNAGATEAREA 6.753500 ;
    ANTENNADIFFAREA 66.508202 ;
    PORT
      LAYER Metal2 ;
        RECT 129.880 0.000 130.280 0.400 ;
    END
  END FrameStrobe[9]
  PIN FrameStrobe_O[0]
    DIRECTION OUTPUT ;
    USE SIGNAL ;
    ANTENNADIFFAREA 2.724000 ;
    PORT
      LAYER Metal2 ;
        RECT 121.240 215.060 121.640 215.460 ;
    END
  END FrameStrobe_O[0]
  PIN FrameStrobe_O[10]
    DIRECTION OUTPUT ;
    USE SIGNAL ;
    ANTENNADIFFAREA 2.724000 ;
    PORT
      LAYER Metal2 ;
        RECT 130.840 215.060 131.240 215.460 ;
    END
  END FrameStrobe_O[10]
  PIN FrameStrobe_O[11]
    DIRECTION OUTPUT ;
    USE SIGNAL ;
    ANTENNADIFFAREA 2.724000 ;
    PORT
      LAYER Metal2 ;
        RECT 131.800 215.060 132.200 215.460 ;
    END
  END FrameStrobe_O[11]
  PIN FrameStrobe_O[12]
    DIRECTION OUTPUT ;
    USE SIGNAL ;
    ANTENNADIFFAREA 2.724000 ;
    PORT
      LAYER Metal2 ;
        RECT 132.760 215.060 133.160 215.460 ;
    END
  END FrameStrobe_O[12]
  PIN FrameStrobe_O[13]
    DIRECTION OUTPUT ;
    USE SIGNAL ;
    ANTENNADIFFAREA 2.724000 ;
    PORT
      LAYER Metal2 ;
        RECT 133.720 215.060 134.120 215.460 ;
    END
  END FrameStrobe_O[13]
  PIN FrameStrobe_O[14]
    DIRECTION OUTPUT ;
    USE SIGNAL ;
    ANTENNADIFFAREA 2.724000 ;
    PORT
      LAYER Metal2 ;
        RECT 134.680 215.060 135.080 215.460 ;
    END
  END FrameStrobe_O[14]
  PIN FrameStrobe_O[15]
    DIRECTION OUTPUT ;
    USE SIGNAL ;
    ANTENNADIFFAREA 2.724000 ;
    PORT
      LAYER Metal2 ;
        RECT 135.640 215.060 136.040 215.460 ;
    END
  END FrameStrobe_O[15]
  PIN FrameStrobe_O[16]
    DIRECTION OUTPUT ;
    USE SIGNAL ;
    ANTENNADIFFAREA 2.724000 ;
    PORT
      LAYER Metal2 ;
        RECT 136.600 215.060 137.000 215.460 ;
    END
  END FrameStrobe_O[16]
  PIN FrameStrobe_O[17]
    DIRECTION OUTPUT ;
    USE SIGNAL ;
    ANTENNADIFFAREA 2.724000 ;
    PORT
      LAYER Metal2 ;
        RECT 137.560 215.060 137.960 215.460 ;
    END
  END FrameStrobe_O[17]
  PIN FrameStrobe_O[18]
    DIRECTION OUTPUT ;
    USE SIGNAL ;
    ANTENNADIFFAREA 2.724000 ;
    PORT
      LAYER Metal2 ;
        RECT 138.520 215.060 138.920 215.460 ;
    END
  END FrameStrobe_O[18]
  PIN FrameStrobe_O[19]
    DIRECTION OUTPUT ;
    USE SIGNAL ;
    ANTENNADIFFAREA 2.724000 ;
    PORT
      LAYER Metal2 ;
        RECT 139.480 215.060 139.880 215.460 ;
    END
  END FrameStrobe_O[19]
  PIN FrameStrobe_O[1]
    DIRECTION OUTPUT ;
    USE SIGNAL ;
    ANTENNADIFFAREA 2.724000 ;
    PORT
      LAYER Metal2 ;
        RECT 122.200 215.060 122.600 215.460 ;
    END
  END FrameStrobe_O[1]
  PIN FrameStrobe_O[2]
    DIRECTION OUTPUT ;
    USE SIGNAL ;
    ANTENNADIFFAREA 2.724000 ;
    PORT
      LAYER Metal2 ;
        RECT 123.160 215.060 123.560 215.460 ;
    END
  END FrameStrobe_O[2]
  PIN FrameStrobe_O[3]
    DIRECTION OUTPUT ;
    USE SIGNAL ;
    ANTENNADIFFAREA 2.724000 ;
    PORT
      LAYER Metal2 ;
        RECT 124.120 215.060 124.520 215.460 ;
    END
  END FrameStrobe_O[3]
  PIN FrameStrobe_O[4]
    DIRECTION OUTPUT ;
    USE SIGNAL ;
    ANTENNADIFFAREA 2.724000 ;
    PORT
      LAYER Metal2 ;
        RECT 125.080 215.060 125.480 215.460 ;
    END
  END FrameStrobe_O[4]
  PIN FrameStrobe_O[5]
    DIRECTION OUTPUT ;
    USE SIGNAL ;
    ANTENNADIFFAREA 2.724000 ;
    PORT
      LAYER Metal2 ;
        RECT 126.040 215.060 126.440 215.460 ;
    END
  END FrameStrobe_O[5]
  PIN FrameStrobe_O[6]
    DIRECTION OUTPUT ;
    USE SIGNAL ;
    ANTENNADIFFAREA 2.724000 ;
    PORT
      LAYER Metal2 ;
        RECT 127.000 215.060 127.400 215.460 ;
    END
  END FrameStrobe_O[6]
  PIN FrameStrobe_O[7]
    DIRECTION OUTPUT ;
    USE SIGNAL ;
    ANTENNADIFFAREA 2.724000 ;
    PORT
      LAYER Metal2 ;
        RECT 127.960 215.060 128.360 215.460 ;
    END
  END FrameStrobe_O[7]
  PIN FrameStrobe_O[8]
    DIRECTION OUTPUT ;
    USE SIGNAL ;
    ANTENNADIFFAREA 2.724000 ;
    PORT
      LAYER Metal2 ;
        RECT 128.920 215.060 129.320 215.460 ;
    END
  END FrameStrobe_O[8]
  PIN FrameStrobe_O[9]
    DIRECTION OUTPUT ;
    USE SIGNAL ;
    ANTENNADIFFAREA 2.724000 ;
    PORT
      LAYER Metal2 ;
        RECT 129.880 215.060 130.280 215.460 ;
    END
  END FrameStrobe_O[9]
  PIN N1BEG[0]
    DIRECTION OUTPUT ;
    USE SIGNAL ;
    ANTENNADIFFAREA 2.724000 ;
    PORT
      LAYER Metal2 ;
        RECT 2.200 215.060 2.600 215.460 ;
    END
  END N1BEG[0]
  PIN N1BEG[1]
    DIRECTION OUTPUT ;
    USE SIGNAL ;
    ANTENNADIFFAREA 2.724000 ;
    PORT
      LAYER Metal2 ;
        RECT 3.160 215.060 3.560 215.460 ;
    END
  END N1BEG[1]
  PIN N1BEG[2]
    DIRECTION OUTPUT ;
    USE SIGNAL ;
    ANTENNADIFFAREA 2.724000 ;
    PORT
      LAYER Metal2 ;
        RECT 4.120 215.060 4.520 215.460 ;
    END
  END N1BEG[2]
  PIN N1BEG[3]
    DIRECTION OUTPUT ;
    USE SIGNAL ;
    ANTENNADIFFAREA 2.724000 ;
    PORT
      LAYER Metal2 ;
        RECT 5.080 215.060 5.480 215.460 ;
    END
  END N1BEG[3]
  PIN N1END[0]
    DIRECTION INPUT ;
    USE SIGNAL ;
    ANTENNAGATEAREA 1.311700 ;
    ANTENNADIFFAREA 12.092400 ;
    PORT
      LAYER Metal2 ;
        RECT 2.200 0.000 2.600 0.400 ;
    END
  END N1END[0]
  PIN N1END[1]
    DIRECTION INPUT ;
    USE SIGNAL ;
    ANTENNAGATEAREA 1.311700 ;
    ANTENNADIFFAREA 12.092400 ;
    PORT
      LAYER Metal2 ;
        RECT 3.160 0.000 3.560 0.400 ;
    END
  END N1END[1]
  PIN N1END[2]
    DIRECTION INPUT ;
    USE SIGNAL ;
    ANTENNAGATEAREA 1.311700 ;
    ANTENNADIFFAREA 12.092400 ;
    PORT
      LAYER Metal2 ;
        RECT 4.120 0.000 4.520 0.400 ;
    END
  END N1END[2]
  PIN N1END[3]
    DIRECTION INPUT ;
    USE SIGNAL ;
    ANTENNAGATEAREA 1.311700 ;
    ANTENNADIFFAREA 12.092400 ;
    PORT
      LAYER Metal2 ;
        RECT 5.080 0.000 5.480 0.400 ;
    END
  END N1END[3]
  PIN N2BEG[0]
    DIRECTION OUTPUT ;
    USE SIGNAL ;
    ANTENNADIFFAREA 2.724000 ;
    PORT
      LAYER Metal2 ;
        RECT 9.880 215.060 10.280 215.460 ;
    END
  END N2BEG[0]
  PIN N2BEG[1]
    DIRECTION OUTPUT ;
    USE SIGNAL ;
    ANTENNADIFFAREA 2.724000 ;
    PORT
      LAYER Metal2 ;
        RECT 10.840 215.060 11.240 215.460 ;
    END
  END N2BEG[1]
  PIN N2BEG[2]
    DIRECTION OUTPUT ;
    USE SIGNAL ;
    ANTENNADIFFAREA 2.724000 ;
    PORT
      LAYER Metal2 ;
        RECT 11.800 215.060 12.200 215.460 ;
    END
  END N2BEG[2]
  PIN N2BEG[3]
    DIRECTION OUTPUT ;
    USE SIGNAL ;
    ANTENNADIFFAREA 2.724000 ;
    PORT
      LAYER Metal2 ;
        RECT 12.760 215.060 13.160 215.460 ;
    END
  END N2BEG[3]
  PIN N2BEG[4]
    DIRECTION OUTPUT ;
    USE SIGNAL ;
    ANTENNADIFFAREA 2.724000 ;
    PORT
      LAYER Metal2 ;
        RECT 13.720 215.060 14.120 215.460 ;
    END
  END N2BEG[4]
  PIN N2BEG[5]
    DIRECTION OUTPUT ;
    USE SIGNAL ;
    ANTENNADIFFAREA 2.724000 ;
    PORT
      LAYER Metal2 ;
        RECT 14.680 215.060 15.080 215.460 ;
    END
  END N2BEG[5]
  PIN N2BEG[6]
    DIRECTION OUTPUT ;
    USE SIGNAL ;
    ANTENNADIFFAREA 2.724000 ;
    PORT
      LAYER Metal2 ;
        RECT 15.640 215.060 16.040 215.460 ;
    END
  END N2BEG[6]
  PIN N2BEG[7]
    DIRECTION OUTPUT ;
    USE SIGNAL ;
    ANTENNADIFFAREA 2.724000 ;
    PORT
      LAYER Metal2 ;
        RECT 16.600 215.060 17.000 215.460 ;
    END
  END N2BEG[7]
  PIN N2BEGb[0]
    DIRECTION OUTPUT ;
    USE SIGNAL ;
    ANTENNADIFFAREA 2.724000 ;
    PORT
      LAYER Metal2 ;
        RECT 22.360 215.060 22.760 215.460 ;
    END
  END N2BEGb[0]
  PIN N2BEGb[1]
    DIRECTION OUTPUT ;
    USE SIGNAL ;
    ANTENNADIFFAREA 2.724000 ;
    PORT
      LAYER Metal2 ;
        RECT 23.320 215.060 23.720 215.460 ;
    END
  END N2BEGb[1]
  PIN N2BEGb[2]
    DIRECTION OUTPUT ;
    USE SIGNAL ;
    ANTENNADIFFAREA 2.724000 ;
    PORT
      LAYER Metal2 ;
        RECT 24.280 215.060 24.680 215.460 ;
    END
  END N2BEGb[2]
  PIN N2BEGb[3]
    DIRECTION OUTPUT ;
    USE SIGNAL ;
    ANTENNADIFFAREA 2.724000 ;
    PORT
      LAYER Metal2 ;
        RECT 25.240 215.060 25.640 215.460 ;
    END
  END N2BEGb[3]
  PIN N2BEGb[4]
    DIRECTION OUTPUT ;
    USE SIGNAL ;
    ANTENNADIFFAREA 2.724000 ;
    PORT
      LAYER Metal2 ;
        RECT 26.200 215.060 26.600 215.460 ;
    END
  END N2BEGb[4]
  PIN N2BEGb[5]
    DIRECTION OUTPUT ;
    USE SIGNAL ;
    ANTENNADIFFAREA 2.724000 ;
    PORT
      LAYER Metal2 ;
        RECT 27.160 215.060 27.560 215.460 ;
    END
  END N2BEGb[5]
  PIN N2BEGb[6]
    DIRECTION OUTPUT ;
    USE SIGNAL ;
    ANTENNADIFFAREA 2.724000 ;
    PORT
      LAYER Metal2 ;
        RECT 28.120 215.060 28.520 215.460 ;
    END
  END N2BEGb[6]
  PIN N2BEGb[7]
    DIRECTION OUTPUT ;
    USE SIGNAL ;
    ANTENNADIFFAREA 2.724000 ;
    PORT
      LAYER Metal2 ;
        RECT 29.080 215.060 29.480 215.460 ;
    END
  END N2BEGb[7]
  PIN N2END[0]
    DIRECTION INPUT ;
    USE SIGNAL ;
    ANTENNAGATEAREA 0.213200 ;
    ANTENNADIFFAREA 2.015400 ;
    PORT
      LAYER Metal2 ;
        RECT 22.360 0.000 22.760 0.400 ;
    END
  END N2END[0]
  PIN N2END[1]
    DIRECTION INPUT ;
    USE SIGNAL ;
    ANTENNAGATEAREA 0.213200 ;
    ANTENNADIFFAREA 2.015400 ;
    PORT
      LAYER Metal2 ;
        RECT 23.320 0.000 23.720 0.400 ;
    END
  END N2END[1]
  PIN N2END[2]
    DIRECTION INPUT ;
    USE SIGNAL ;
    ANTENNAGATEAREA 0.213200 ;
    ANTENNADIFFAREA 2.015400 ;
    PORT
      LAYER Metal2 ;
        RECT 24.280 0.000 24.680 0.400 ;
    END
  END N2END[2]
  PIN N2END[3]
    DIRECTION INPUT ;
    USE SIGNAL ;
    ANTENNAGATEAREA 0.213200 ;
    ANTENNADIFFAREA 2.015400 ;
    PORT
      LAYER Metal2 ;
        RECT 25.240 0.000 25.640 0.400 ;
    END
  END N2END[3]
  PIN N2END[4]
    DIRECTION INPUT ;
    USE SIGNAL ;
    ANTENNAGATEAREA 0.213200 ;
    ANTENNADIFFAREA 2.015400 ;
    PORT
      LAYER Metal2 ;
        RECT 26.200 0.000 26.600 0.400 ;
    END
  END N2END[4]
  PIN N2END[5]
    DIRECTION INPUT ;
    USE SIGNAL ;
    ANTENNAGATEAREA 0.213200 ;
    ANTENNADIFFAREA 2.015400 ;
    PORT
      LAYER Metal2 ;
        RECT 27.160 0.000 27.560 0.400 ;
    END
  END N2END[5]
  PIN N2END[6]
    DIRECTION INPUT ;
    USE SIGNAL ;
    ANTENNAGATEAREA 0.213200 ;
    ANTENNADIFFAREA 2.015400 ;
    PORT
      LAYER Metal2 ;
        RECT 28.120 0.000 28.520 0.400 ;
    END
  END N2END[6]
  PIN N2END[7]
    DIRECTION INPUT ;
    USE SIGNAL ;
    ANTENNAGATEAREA 0.213200 ;
    ANTENNADIFFAREA 2.015400 ;
    PORT
      LAYER Metal2 ;
        RECT 29.080 0.000 29.480 0.400 ;
    END
  END N2END[7]
  PIN N2MID[0]
    DIRECTION INPUT ;
    USE SIGNAL ;
    ANTENNAGATEAREA 0.393900 ;
    ANTENNADIFFAREA 4.030800 ;
    PORT
      LAYER Metal2 ;
        RECT 9.880 0.000 10.280 0.400 ;
    END
  END N2MID[0]
  PIN N2MID[1]
    DIRECTION INPUT ;
    USE SIGNAL ;
    ANTENNAGATEAREA 0.393900 ;
    ANTENNADIFFAREA 4.030800 ;
    PORT
      LAYER Metal2 ;
        RECT 10.840 0.000 11.240 0.400 ;
    END
  END N2MID[1]
  PIN N2MID[2]
    DIRECTION INPUT ;
    USE SIGNAL ;
    ANTENNAGATEAREA 0.393900 ;
    ANTENNADIFFAREA 4.030800 ;
    PORT
      LAYER Metal2 ;
        RECT 11.800 0.000 12.200 0.400 ;
    END
  END N2MID[2]
  PIN N2MID[3]
    DIRECTION INPUT ;
    USE SIGNAL ;
    ANTENNAGATEAREA 0.393900 ;
    ANTENNADIFFAREA 4.030800 ;
    PORT
      LAYER Metal2 ;
        RECT 12.760 0.000 13.160 0.400 ;
    END
  END N2MID[3]
  PIN N2MID[4]
    DIRECTION INPUT ;
    USE SIGNAL ;
    ANTENNAGATEAREA 0.393900 ;
    ANTENNADIFFAREA 4.030800 ;
    PORT
      LAYER Metal2 ;
        RECT 13.720 0.000 14.120 0.400 ;
    END
  END N2MID[4]
  PIN N2MID[5]
    DIRECTION INPUT ;
    USE SIGNAL ;
    ANTENNAGATEAREA 0.393900 ;
    ANTENNADIFFAREA 4.030800 ;
    PORT
      LAYER Metal2 ;
        RECT 14.680 0.000 15.080 0.400 ;
    END
  END N2MID[5]
  PIN N2MID[6]
    DIRECTION INPUT ;
    USE SIGNAL ;
    ANTENNAGATEAREA 0.393900 ;
    ANTENNADIFFAREA 4.030800 ;
    PORT
      LAYER Metal2 ;
        RECT 15.640 0.000 16.040 0.400 ;
    END
  END N2MID[6]
  PIN N2MID[7]
    DIRECTION INPUT ;
    USE SIGNAL ;
    ANTENNAGATEAREA 0.393900 ;
    ANTENNADIFFAREA 4.030800 ;
    PORT
      LAYER Metal2 ;
        RECT 16.600 0.000 17.000 0.400 ;
    END
  END N2MID[7]
  PIN N4BEG[0]
    DIRECTION OUTPUT ;
    USE SIGNAL ;
    ANTENNADIFFAREA 2.724000 ;
    PORT
      LAYER Metal2 ;
        RECT 37.720 215.060 38.120 215.460 ;
    END
  END N4BEG[0]
  PIN N4BEG[10]
    DIRECTION OUTPUT ;
    USE SIGNAL ;
    ANTENNADIFFAREA 2.724000 ;
    PORT
      LAYER Metal2 ;
        RECT 47.320 215.060 47.720 215.460 ;
    END
  END N4BEG[10]
  PIN N4BEG[11]
    DIRECTION OUTPUT ;
    USE SIGNAL ;
    ANTENNADIFFAREA 2.724000 ;
    PORT
      LAYER Metal2 ;
        RECT 48.280 215.060 48.680 215.460 ;
    END
  END N4BEG[11]
  PIN N4BEG[12]
    DIRECTION OUTPUT ;
    USE SIGNAL ;
    ANTENNADIFFAREA 2.724000 ;
    PORT
      LAYER Metal2 ;
        RECT 49.240 215.060 49.640 215.460 ;
    END
  END N4BEG[12]
  PIN N4BEG[13]
    DIRECTION OUTPUT ;
    USE SIGNAL ;
    ANTENNADIFFAREA 2.724000 ;
    PORT
      LAYER Metal2 ;
        RECT 50.200 215.060 50.600 215.460 ;
    END
  END N4BEG[13]
  PIN N4BEG[14]
    DIRECTION OUTPUT ;
    USE SIGNAL ;
    ANTENNADIFFAREA 2.724000 ;
    PORT
      LAYER Metal2 ;
        RECT 51.160 215.060 51.560 215.460 ;
    END
  END N4BEG[14]
  PIN N4BEG[15]
    DIRECTION OUTPUT ;
    USE SIGNAL ;
    ANTENNADIFFAREA 2.724000 ;
    PORT
      LAYER Metal2 ;
        RECT 52.120 215.060 52.520 215.460 ;
    END
  END N4BEG[15]
  PIN N4BEG[1]
    DIRECTION OUTPUT ;
    USE SIGNAL ;
    ANTENNADIFFAREA 2.724000 ;
    PORT
      LAYER Metal2 ;
        RECT 38.680 215.060 39.080 215.460 ;
    END
  END N4BEG[1]
  PIN N4BEG[2]
    DIRECTION OUTPUT ;
    USE SIGNAL ;
    ANTENNADIFFAREA 2.724000 ;
    PORT
      LAYER Metal2 ;
        RECT 39.640 215.060 40.040 215.460 ;
    END
  END N4BEG[2]
  PIN N4BEG[3]
    DIRECTION OUTPUT ;
    USE SIGNAL ;
    ANTENNADIFFAREA 2.724000 ;
    PORT
      LAYER Metal2 ;
        RECT 40.600 215.060 41.000 215.460 ;
    END
  END N4BEG[3]
  PIN N4BEG[4]
    DIRECTION OUTPUT ;
    USE SIGNAL ;
    ANTENNADIFFAREA 2.724000 ;
    PORT
      LAYER Metal2 ;
        RECT 41.560 215.060 41.960 215.460 ;
    END
  END N4BEG[4]
  PIN N4BEG[5]
    DIRECTION OUTPUT ;
    USE SIGNAL ;
    ANTENNADIFFAREA 2.724000 ;
    PORT
      LAYER Metal2 ;
        RECT 42.520 215.060 42.920 215.460 ;
    END
  END N4BEG[5]
  PIN N4BEG[6]
    DIRECTION OUTPUT ;
    USE SIGNAL ;
    ANTENNADIFFAREA 2.724000 ;
    PORT
      LAYER Metal2 ;
        RECT 43.480 215.060 43.880 215.460 ;
    END
  END N4BEG[6]
  PIN N4BEG[7]
    DIRECTION OUTPUT ;
    USE SIGNAL ;
    ANTENNADIFFAREA 2.724000 ;
    PORT
      LAYER Metal2 ;
        RECT 44.440 215.060 44.840 215.460 ;
    END
  END N4BEG[7]
  PIN N4BEG[8]
    DIRECTION OUTPUT ;
    USE SIGNAL ;
    ANTENNADIFFAREA 2.724000 ;
    PORT
      LAYER Metal2 ;
        RECT 45.400 215.060 45.800 215.460 ;
    END
  END N4BEG[8]
  PIN N4BEG[9]
    DIRECTION OUTPUT ;
    USE SIGNAL ;
    ANTENNADIFFAREA 2.724000 ;
    PORT
      LAYER Metal2 ;
        RECT 46.360 215.060 46.760 215.460 ;
    END
  END N4BEG[9]
  PIN N4END[0]
    DIRECTION INPUT ;
    USE SIGNAL ;
    ANTENNAGATEAREA 1.066000 ;
    ANTENNADIFFAREA 10.077000 ;
    PORT
      LAYER Metal2 ;
        RECT 37.720 0.000 38.120 0.400 ;
    END
  END N4END[0]
  PIN N4END[10]
    DIRECTION INPUT ;
    USE SIGNAL ;
    ANTENNAGATEAREA 0.180700 ;
    ANTENNADIFFAREA 2.015400 ;
    PORT
      LAYER Metal2 ;
        RECT 47.320 0.000 47.720 0.400 ;
    END
  END N4END[10]
  PIN N4END[11]
    DIRECTION INPUT ;
    USE SIGNAL ;
    ANTENNAGATEAREA 0.180700 ;
    ANTENNADIFFAREA 2.015400 ;
    PORT
      LAYER Metal2 ;
        RECT 48.280 0.000 48.680 0.400 ;
    END
  END N4END[11]
  PIN N4END[12]
    DIRECTION INPUT ;
    USE SIGNAL ;
    ANTENNAGATEAREA 0.180700 ;
    ANTENNADIFFAREA 2.015400 ;
    PORT
      LAYER Metal2 ;
        RECT 49.240 0.000 49.640 0.400 ;
    END
  END N4END[12]
  PIN N4END[13]
    DIRECTION INPUT ;
    USE SIGNAL ;
    ANTENNAGATEAREA 0.180700 ;
    ANTENNADIFFAREA 2.015400 ;
    PORT
      LAYER Metal2 ;
        RECT 50.200 0.000 50.600 0.400 ;
    END
  END N4END[13]
  PIN N4END[14]
    DIRECTION INPUT ;
    USE SIGNAL ;
    ANTENNAGATEAREA 0.180700 ;
    ANTENNADIFFAREA 4.030800 ;
    PORT
      LAYER Metal2 ;
        RECT 51.160 0.000 51.560 0.400 ;
    END
  END N4END[14]
  PIN N4END[15]
    DIRECTION INPUT ;
    USE SIGNAL ;
    ANTENNAGATEAREA 0.180700 ;
    ANTENNADIFFAREA 2.015400 ;
    PORT
      LAYER Metal2 ;
        RECT 52.120 0.000 52.520 0.400 ;
    END
  END N4END[15]
  PIN N4END[1]
    DIRECTION INPUT ;
    USE SIGNAL ;
    ANTENNAGATEAREA 1.066000 ;
    ANTENNADIFFAREA 10.077000 ;
    PORT
      LAYER Metal2 ;
        RECT 38.680 0.000 39.080 0.400 ;
    END
  END N4END[1]
  PIN N4END[2]
    DIRECTION INPUT ;
    USE SIGNAL ;
    ANTENNAGATEAREA 1.066000 ;
    ANTENNADIFFAREA 10.077000 ;
    PORT
      LAYER Metal2 ;
        RECT 39.640 0.000 40.040 0.400 ;
    END
  END N4END[2]
  PIN N4END[3]
    DIRECTION INPUT ;
    USE SIGNAL ;
    ANTENNAGATEAREA 1.066000 ;
    ANTENNADIFFAREA 10.077000 ;
    PORT
      LAYER Metal2 ;
        RECT 40.600 0.000 41.000 0.400 ;
    END
  END N4END[3]
  PIN N4END[4]
    DIRECTION INPUT ;
    USE SIGNAL ;
    ANTENNAGATEAREA 0.180700 ;
    ANTENNADIFFAREA 2.015400 ;
    PORT
      LAYER Metal2 ;
        RECT 41.560 0.000 41.960 0.400 ;
    END
  END N4END[4]
  PIN N4END[5]
    DIRECTION INPUT ;
    USE SIGNAL ;
    ANTENNAGATEAREA 0.180700 ;
    ANTENNADIFFAREA 2.015400 ;
    PORT
      LAYER Metal2 ;
        RECT 42.520 0.000 42.920 0.400 ;
    END
  END N4END[5]
  PIN N4END[6]
    DIRECTION INPUT ;
    USE SIGNAL ;
    ANTENNAGATEAREA 0.180700 ;
    ANTENNADIFFAREA 2.015400 ;
    PORT
      LAYER Metal2 ;
        RECT 43.480 0.000 43.880 0.400 ;
    END
  END N4END[6]
  PIN N4END[7]
    DIRECTION INPUT ;
    USE SIGNAL ;
    ANTENNAGATEAREA 0.180700 ;
    ANTENNADIFFAREA 2.015400 ;
    PORT
      LAYER Metal2 ;
        RECT 44.440 0.000 44.840 0.400 ;
    END
  END N4END[7]
  PIN N4END[8]
    DIRECTION INPUT ;
    USE SIGNAL ;
    ANTENNAGATEAREA 0.180700 ;
    ANTENNADIFFAREA 2.015400 ;
    PORT
      LAYER Metal2 ;
        RECT 45.400 0.000 45.800 0.400 ;
    END
  END N4END[8]
  PIN N4END[9]
    DIRECTION INPUT ;
    USE SIGNAL ;
    ANTENNAGATEAREA 0.180700 ;
    ANTENNADIFFAREA 2.015400 ;
    PORT
      LAYER Metal2 ;
        RECT 46.360 0.000 46.760 0.400 ;
    END
  END N4END[9]
  PIN RAM2FAB_D0_I0
    DIRECTION INPUT ;
    USE SIGNAL ;
    ANTENNAGATEAREA 0.335400 ;
    ANTENNADIFFAREA 4.030800 ;
    PORT
      LAYER Metal3 ;
        RECT 0.000 89.260 0.400 89.660 ;
    END
  END RAM2FAB_D0_I0
  PIN RAM2FAB_D0_I1
    DIRECTION INPUT ;
    USE SIGNAL ;
    ANTENNAGATEAREA 0.335400 ;
    ANTENNADIFFAREA 4.030800 ;
    PORT
      LAYER Metal3 ;
        RECT 0.000 91.780 0.400 92.180 ;
    END
  END RAM2FAB_D0_I1
  PIN RAM2FAB_D0_I2
    DIRECTION INPUT ;
    USE SIGNAL ;
    ANTENNAGATEAREA 0.335400 ;
    ANTENNADIFFAREA 4.030800 ;
    PORT
      LAYER Metal3 ;
        RECT 0.000 94.300 0.400 94.700 ;
    END
  END RAM2FAB_D0_I2
  PIN RAM2FAB_D0_I3
    DIRECTION INPUT ;
    USE SIGNAL ;
    ANTENNAGATEAREA 0.335400 ;
    ANTENNADIFFAREA 4.030800 ;
    PORT
      LAYER Metal3 ;
        RECT 0.000 96.820 0.400 97.220 ;
    END
  END RAM2FAB_D0_I3
  PIN RAM2FAB_D1_I0
    DIRECTION INPUT ;
    USE SIGNAL ;
    ANTENNAGATEAREA 0.335400 ;
    ANTENNADIFFAREA 4.030800 ;
    PORT
      LAYER Metal3 ;
        RECT 0.000 99.340 0.400 99.740 ;
    END
  END RAM2FAB_D1_I0
  PIN RAM2FAB_D1_I1
    DIRECTION INPUT ;
    USE SIGNAL ;
    ANTENNAGATEAREA 0.335400 ;
    ANTENNADIFFAREA 4.030800 ;
    PORT
      LAYER Metal3 ;
        RECT 0.000 101.860 0.400 102.260 ;
    END
  END RAM2FAB_D1_I1
  PIN RAM2FAB_D1_I2
    DIRECTION INPUT ;
    USE SIGNAL ;
    ANTENNAGATEAREA 0.335400 ;
    ANTENNADIFFAREA 4.030800 ;
    PORT
      LAYER Metal3 ;
        RECT 0.000 104.380 0.400 104.780 ;
    END
  END RAM2FAB_D1_I2
  PIN RAM2FAB_D1_I3
    DIRECTION INPUT ;
    USE SIGNAL ;
    ANTENNAGATEAREA 0.335400 ;
    ANTENNADIFFAREA 4.030800 ;
    PORT
      LAYER Metal3 ;
        RECT 0.000 106.900 0.400 107.300 ;
    END
  END RAM2FAB_D1_I3
  PIN RAM2FAB_D2_I0
    DIRECTION INPUT ;
    USE SIGNAL ;
    ANTENNAGATEAREA 0.335400 ;
    ANTENNADIFFAREA 4.030800 ;
    PORT
      LAYER Metal3 ;
        RECT 0.000 110.260 0.400 110.660 ;
    END
  END RAM2FAB_D2_I0
  PIN RAM2FAB_D2_I1
    DIRECTION INPUT ;
    USE SIGNAL ;
    ANTENNAGATEAREA 0.335400 ;
    ANTENNADIFFAREA 4.030800 ;
    PORT
      LAYER Metal3 ;
        RECT 0.000 112.780 0.400 113.180 ;
    END
  END RAM2FAB_D2_I1
  PIN RAM2FAB_D2_I2
    DIRECTION INPUT ;
    USE SIGNAL ;
    ANTENNAGATEAREA 0.335400 ;
    ANTENNADIFFAREA 4.030800 ;
    PORT
      LAYER Metal3 ;
        RECT 0.000 115.300 0.400 115.700 ;
    END
  END RAM2FAB_D2_I2
  PIN RAM2FAB_D2_I3
    DIRECTION INPUT ;
    USE SIGNAL ;
    ANTENNAGATEAREA 0.335400 ;
    ANTENNADIFFAREA 4.030800 ;
    PORT
      LAYER Metal3 ;
        RECT 0.000 117.820 0.400 118.220 ;
    END
  END RAM2FAB_D2_I3
  PIN RAM2FAB_D3_I0
    DIRECTION INPUT ;
    USE SIGNAL ;
    ANTENNAGATEAREA 0.335400 ;
    ANTENNADIFFAREA 4.030800 ;
    PORT
      LAYER Metal3 ;
        RECT 0.000 120.340 0.400 120.740 ;
    END
  END RAM2FAB_D3_I0
  PIN RAM2FAB_D3_I1
    DIRECTION INPUT ;
    USE SIGNAL ;
    ANTENNAGATEAREA 0.335400 ;
    ANTENNADIFFAREA 4.030800 ;
    PORT
      LAYER Metal3 ;
        RECT 0.000 122.860 0.400 123.260 ;
    END
  END RAM2FAB_D3_I1
  PIN RAM2FAB_D3_I2
    DIRECTION INPUT ;
    USE SIGNAL ;
    ANTENNAGATEAREA 0.335400 ;
    ANTENNADIFFAREA 4.030800 ;
    PORT
      LAYER Metal3 ;
        RECT 0.000 125.380 0.400 125.780 ;
    END
  END RAM2FAB_D3_I2
  PIN RAM2FAB_D3_I3
    DIRECTION INPUT ;
    USE SIGNAL ;
    ANTENNAGATEAREA 0.335400 ;
    ANTENNADIFFAREA 4.030800 ;
    PORT
      LAYER Metal3 ;
        RECT 0.000 127.900 0.400 128.300 ;
    END
  END RAM2FAB_D3_I3
  PIN S1BEG[0]
    DIRECTION OUTPUT ;
    USE SIGNAL ;
    ANTENNADIFFAREA 2.724000 ;
    PORT
      LAYER Metal2 ;
        RECT 58.840 0.000 59.240 0.400 ;
    END
  END S1BEG[0]
  PIN S1BEG[1]
    DIRECTION OUTPUT ;
    USE SIGNAL ;
    ANTENNADIFFAREA 2.724000 ;
    PORT
      LAYER Metal2 ;
        RECT 59.800 0.000 60.200 0.400 ;
    END
  END S1BEG[1]
  PIN S1BEG[2]
    DIRECTION OUTPUT ;
    USE SIGNAL ;
    ANTENNADIFFAREA 2.724000 ;
    PORT
      LAYER Metal2 ;
        RECT 60.760 0.000 61.160 0.400 ;
    END
  END S1BEG[2]
  PIN S1BEG[3]
    DIRECTION OUTPUT ;
    USE SIGNAL ;
    ANTENNADIFFAREA 2.724000 ;
    PORT
      LAYER Metal2 ;
        RECT 61.720 0.000 62.120 0.400 ;
    END
  END S1BEG[3]
  PIN S1END[0]
    DIRECTION INPUT ;
    USE SIGNAL ;
    ANTENNAGATEAREA 1.307800 ;
    ANTENNADIFFAREA 12.092400 ;
    PORT
      LAYER Metal2 ;
        RECT 58.840 215.060 59.240 215.460 ;
    END
  END S1END[0]
  PIN S1END[1]
    DIRECTION INPUT ;
    USE SIGNAL ;
    ANTENNAGATEAREA 1.307800 ;
    ANTENNADIFFAREA 12.092400 ;
    PORT
      LAYER Metal2 ;
        RECT 59.800 215.060 60.200 215.460 ;
    END
  END S1END[1]
  PIN S1END[2]
    DIRECTION INPUT ;
    USE SIGNAL ;
    ANTENNAGATEAREA 1.307800 ;
    ANTENNADIFFAREA 12.092400 ;
    PORT
      LAYER Metal2 ;
        RECT 60.760 215.060 61.160 215.460 ;
    END
  END S1END[2]
  PIN S1END[3]
    DIRECTION INPUT ;
    USE SIGNAL ;
    ANTENNAGATEAREA 1.307800 ;
    ANTENNADIFFAREA 12.092400 ;
    PORT
      LAYER Metal2 ;
        RECT 61.720 215.060 62.120 215.460 ;
    END
  END S1END[3]
  PIN S2BEG[0]
    DIRECTION OUTPUT ;
    USE SIGNAL ;
    ANTENNADIFFAREA 2.724000 ;
    PORT
      LAYER Metal2 ;
        RECT 66.520 0.000 66.920 0.400 ;
    END
  END S2BEG[0]
  PIN S2BEG[1]
    DIRECTION OUTPUT ;
    USE SIGNAL ;
    ANTENNADIFFAREA 2.724000 ;
    PORT
      LAYER Metal2 ;
        RECT 67.480 0.000 67.880 0.400 ;
    END
  END S2BEG[1]
  PIN S2BEG[2]
    DIRECTION OUTPUT ;
    USE SIGNAL ;
    ANTENNADIFFAREA 2.724000 ;
    PORT
      LAYER Metal2 ;
        RECT 68.440 0.000 68.840 0.400 ;
    END
  END S2BEG[2]
  PIN S2BEG[3]
    DIRECTION OUTPUT ;
    USE SIGNAL ;
    ANTENNADIFFAREA 2.724000 ;
    PORT
      LAYER Metal2 ;
        RECT 69.400 0.000 69.800 0.400 ;
    END
  END S2BEG[3]
  PIN S2BEG[4]
    DIRECTION OUTPUT ;
    USE SIGNAL ;
    ANTENNADIFFAREA 2.724000 ;
    PORT
      LAYER Metal2 ;
        RECT 70.360 0.000 70.760 0.400 ;
    END
  END S2BEG[4]
  PIN S2BEG[5]
    DIRECTION OUTPUT ;
    USE SIGNAL ;
    ANTENNADIFFAREA 2.724000 ;
    PORT
      LAYER Metal2 ;
        RECT 71.320 0.000 71.720 0.400 ;
    END
  END S2BEG[5]
  PIN S2BEG[6]
    DIRECTION OUTPUT ;
    USE SIGNAL ;
    ANTENNADIFFAREA 2.724000 ;
    PORT
      LAYER Metal2 ;
        RECT 72.280 0.000 72.680 0.400 ;
    END
  END S2BEG[6]
  PIN S2BEG[7]
    DIRECTION OUTPUT ;
    USE SIGNAL ;
    ANTENNADIFFAREA 2.724000 ;
    PORT
      LAYER Metal2 ;
        RECT 73.240 0.000 73.640 0.400 ;
    END
  END S2BEG[7]
  PIN S2BEGb[0]
    DIRECTION OUTPUT ;
    USE SIGNAL ;
    ANTENNADIFFAREA 2.724000 ;
    PORT
      LAYER Metal2 ;
        RECT 79.000 0.000 79.400 0.400 ;
    END
  END S2BEGb[0]
  PIN S2BEGb[1]
    DIRECTION OUTPUT ;
    USE SIGNAL ;
    ANTENNADIFFAREA 2.724000 ;
    PORT
      LAYER Metal2 ;
        RECT 79.960 0.000 80.360 0.400 ;
    END
  END S2BEGb[1]
  PIN S2BEGb[2]
    DIRECTION OUTPUT ;
    USE SIGNAL ;
    ANTENNADIFFAREA 2.724000 ;
    PORT
      LAYER Metal2 ;
        RECT 80.920 0.000 81.320 0.400 ;
    END
  END S2BEGb[2]
  PIN S2BEGb[3]
    DIRECTION OUTPUT ;
    USE SIGNAL ;
    ANTENNADIFFAREA 2.724000 ;
    PORT
      LAYER Metal2 ;
        RECT 81.880 0.000 82.280 0.400 ;
    END
  END S2BEGb[3]
  PIN S2BEGb[4]
    DIRECTION OUTPUT ;
    USE SIGNAL ;
    ANTENNADIFFAREA 2.724000 ;
    PORT
      LAYER Metal2 ;
        RECT 82.840 0.000 83.240 0.400 ;
    END
  END S2BEGb[4]
  PIN S2BEGb[5]
    DIRECTION OUTPUT ;
    USE SIGNAL ;
    ANTENNADIFFAREA 2.724000 ;
    PORT
      LAYER Metal2 ;
        RECT 83.800 0.000 84.200 0.400 ;
    END
  END S2BEGb[5]
  PIN S2BEGb[6]
    DIRECTION OUTPUT ;
    USE SIGNAL ;
    ANTENNADIFFAREA 2.724000 ;
    PORT
      LAYER Metal2 ;
        RECT 84.760 0.000 85.160 0.400 ;
    END
  END S2BEGb[6]
  PIN S2BEGb[7]
    DIRECTION OUTPUT ;
    USE SIGNAL ;
    ANTENNADIFFAREA 2.724000 ;
    PORT
      LAYER Metal2 ;
        RECT 85.720 0.000 86.120 0.400 ;
    END
  END S2BEGb[7]
  PIN S2END[0]
    DIRECTION INPUT ;
    USE SIGNAL ;
    ANTENNAGATEAREA 0.213200 ;
    ANTENNADIFFAREA 2.015400 ;
    PORT
      LAYER Metal2 ;
        RECT 79.000 215.060 79.400 215.460 ;
    END
  END S2END[0]
  PIN S2END[1]
    DIRECTION INPUT ;
    USE SIGNAL ;
    ANTENNAGATEAREA 0.213200 ;
    ANTENNADIFFAREA 2.015400 ;
    PORT
      LAYER Metal2 ;
        RECT 79.960 215.060 80.360 215.460 ;
    END
  END S2END[1]
  PIN S2END[2]
    DIRECTION INPUT ;
    USE SIGNAL ;
    ANTENNAGATEAREA 0.213200 ;
    ANTENNADIFFAREA 2.015400 ;
    PORT
      LAYER Metal2 ;
        RECT 80.920 215.060 81.320 215.460 ;
    END
  END S2END[2]
  PIN S2END[3]
    DIRECTION INPUT ;
    USE SIGNAL ;
    ANTENNAGATEAREA 0.213200 ;
    ANTENNADIFFAREA 2.015400 ;
    PORT
      LAYER Metal2 ;
        RECT 81.880 215.060 82.280 215.460 ;
    END
  END S2END[3]
  PIN S2END[4]
    DIRECTION INPUT ;
    USE SIGNAL ;
    ANTENNAGATEAREA 0.213200 ;
    ANTENNADIFFAREA 2.015400 ;
    PORT
      LAYER Metal2 ;
        RECT 82.840 215.060 83.240 215.460 ;
    END
  END S2END[4]
  PIN S2END[5]
    DIRECTION INPUT ;
    USE SIGNAL ;
    ANTENNAGATEAREA 0.213200 ;
    ANTENNADIFFAREA 2.015400 ;
    PORT
      LAYER Metal2 ;
        RECT 83.800 215.060 84.200 215.460 ;
    END
  END S2END[5]
  PIN S2END[6]
    DIRECTION INPUT ;
    USE SIGNAL ;
    ANTENNAGATEAREA 0.213200 ;
    ANTENNADIFFAREA 2.015400 ;
    PORT
      LAYER Metal2 ;
        RECT 84.760 215.060 85.160 215.460 ;
    END
  END S2END[6]
  PIN S2END[7]
    DIRECTION INPUT ;
    USE SIGNAL ;
    ANTENNAGATEAREA 0.213200 ;
    ANTENNADIFFAREA 2.015400 ;
    PORT
      LAYER Metal2 ;
        RECT 85.720 215.060 86.120 215.460 ;
    END
  END S2END[7]
  PIN S2MID[0]
    DIRECTION INPUT ;
    USE SIGNAL ;
    ANTENNAGATEAREA 0.393900 ;
    ANTENNADIFFAREA 4.030800 ;
    PORT
      LAYER Metal2 ;
        RECT 66.520 215.060 66.920 215.460 ;
    END
  END S2MID[0]
  PIN S2MID[1]
    DIRECTION INPUT ;
    USE SIGNAL ;
    ANTENNAGATEAREA 0.393900 ;
    ANTENNADIFFAREA 4.030800 ;
    PORT
      LAYER Metal2 ;
        RECT 67.480 215.060 67.880 215.460 ;
    END
  END S2MID[1]
  PIN S2MID[2]
    DIRECTION INPUT ;
    USE SIGNAL ;
    ANTENNAGATEAREA 0.393900 ;
    ANTENNADIFFAREA 4.030800 ;
    PORT
      LAYER Metal2 ;
        RECT 68.440 215.060 68.840 215.460 ;
    END
  END S2MID[2]
  PIN S2MID[3]
    DIRECTION INPUT ;
    USE SIGNAL ;
    ANTENNAGATEAREA 0.393900 ;
    ANTENNADIFFAREA 4.030800 ;
    PORT
      LAYER Metal2 ;
        RECT 69.400 215.060 69.800 215.460 ;
    END
  END S2MID[3]
  PIN S2MID[4]
    DIRECTION INPUT ;
    USE SIGNAL ;
    ANTENNAGATEAREA 0.393900 ;
    ANTENNADIFFAREA 4.030800 ;
    PORT
      LAYER Metal2 ;
        RECT 70.360 215.060 70.760 215.460 ;
    END
  END S2MID[4]
  PIN S2MID[5]
    DIRECTION INPUT ;
    USE SIGNAL ;
    ANTENNAGATEAREA 0.393900 ;
    ANTENNADIFFAREA 4.030800 ;
    PORT
      LAYER Metal2 ;
        RECT 71.320 215.060 71.720 215.460 ;
    END
  END S2MID[5]
  PIN S2MID[6]
    DIRECTION INPUT ;
    USE SIGNAL ;
    ANTENNAGATEAREA 0.393900 ;
    ANTENNADIFFAREA 4.030800 ;
    PORT
      LAYER Metal2 ;
        RECT 72.280 215.060 72.680 215.460 ;
    END
  END S2MID[6]
  PIN S2MID[7]
    DIRECTION INPUT ;
    USE SIGNAL ;
    ANTENNAGATEAREA 0.393900 ;
    ANTENNADIFFAREA 4.030800 ;
    PORT
      LAYER Metal2 ;
        RECT 73.240 215.060 73.640 215.460 ;
    END
  END S2MID[7]
  PIN S4BEG[0]
    DIRECTION OUTPUT ;
    USE SIGNAL ;
    ANTENNADIFFAREA 2.724000 ;
    PORT
      LAYER Metal2 ;
        RECT 94.360 0.000 94.760 0.400 ;
    END
  END S4BEG[0]
  PIN S4BEG[10]
    DIRECTION OUTPUT ;
    USE SIGNAL ;
    ANTENNADIFFAREA 2.724000 ;
    PORT
      LAYER Metal2 ;
        RECT 103.960 0.000 104.360 0.400 ;
    END
  END S4BEG[10]
  PIN S4BEG[11]
    DIRECTION OUTPUT ;
    USE SIGNAL ;
    ANTENNADIFFAREA 2.724000 ;
    PORT
      LAYER Metal2 ;
        RECT 104.920 0.000 105.320 0.400 ;
    END
  END S4BEG[11]
  PIN S4BEG[12]
    DIRECTION OUTPUT ;
    USE SIGNAL ;
    ANTENNADIFFAREA 2.724000 ;
    PORT
      LAYER Metal2 ;
        RECT 105.880 0.000 106.280 0.400 ;
    END
  END S4BEG[12]
  PIN S4BEG[13]
    DIRECTION OUTPUT ;
    USE SIGNAL ;
    ANTENNADIFFAREA 2.724000 ;
    PORT
      LAYER Metal2 ;
        RECT 106.840 0.000 107.240 0.400 ;
    END
  END S4BEG[13]
  PIN S4BEG[14]
    DIRECTION OUTPUT ;
    USE SIGNAL ;
    ANTENNADIFFAREA 2.724000 ;
    PORT
      LAYER Metal2 ;
        RECT 107.800 0.000 108.200 0.400 ;
    END
  END S4BEG[14]
  PIN S4BEG[15]
    DIRECTION OUTPUT ;
    USE SIGNAL ;
    ANTENNADIFFAREA 2.724000 ;
    PORT
      LAYER Metal2 ;
        RECT 108.760 0.000 109.160 0.400 ;
    END
  END S4BEG[15]
  PIN S4BEG[1]
    DIRECTION OUTPUT ;
    USE SIGNAL ;
    ANTENNADIFFAREA 2.724000 ;
    PORT
      LAYER Metal2 ;
        RECT 95.320 0.000 95.720 0.400 ;
    END
  END S4BEG[1]
  PIN S4BEG[2]
    DIRECTION OUTPUT ;
    USE SIGNAL ;
    ANTENNADIFFAREA 2.724000 ;
    PORT
      LAYER Metal2 ;
        RECT 96.280 0.000 96.680 0.400 ;
    END
  END S4BEG[2]
  PIN S4BEG[3]
    DIRECTION OUTPUT ;
    USE SIGNAL ;
    ANTENNADIFFAREA 2.724000 ;
    PORT
      LAYER Metal2 ;
        RECT 97.240 0.000 97.640 0.400 ;
    END
  END S4BEG[3]
  PIN S4BEG[4]
    DIRECTION OUTPUT ;
    USE SIGNAL ;
    ANTENNADIFFAREA 2.724000 ;
    PORT
      LAYER Metal2 ;
        RECT 98.200 0.000 98.600 0.400 ;
    END
  END S4BEG[4]
  PIN S4BEG[5]
    DIRECTION OUTPUT ;
    USE SIGNAL ;
    ANTENNADIFFAREA 2.724000 ;
    PORT
      LAYER Metal2 ;
        RECT 99.160 0.000 99.560 0.400 ;
    END
  END S4BEG[5]
  PIN S4BEG[6]
    DIRECTION OUTPUT ;
    USE SIGNAL ;
    ANTENNADIFFAREA 2.724000 ;
    PORT
      LAYER Metal2 ;
        RECT 100.120 0.000 100.520 0.400 ;
    END
  END S4BEG[6]
  PIN S4BEG[7]
    DIRECTION OUTPUT ;
    USE SIGNAL ;
    ANTENNADIFFAREA 2.724000 ;
    PORT
      LAYER Metal2 ;
        RECT 101.080 0.000 101.480 0.400 ;
    END
  END S4BEG[7]
  PIN S4BEG[8]
    DIRECTION OUTPUT ;
    USE SIGNAL ;
    ANTENNADIFFAREA 2.724000 ;
    PORT
      LAYER Metal2 ;
        RECT 102.040 0.000 102.440 0.400 ;
    END
  END S4BEG[8]
  PIN S4BEG[9]
    DIRECTION OUTPUT ;
    USE SIGNAL ;
    ANTENNADIFFAREA 2.724000 ;
    PORT
      LAYER Metal2 ;
        RECT 103.000 0.000 103.400 0.400 ;
    END
  END S4BEG[9]
  PIN S4END[0]
    DIRECTION INPUT ;
    USE SIGNAL ;
    ANTENNAGATEAREA 1.066000 ;
    ANTENNADIFFAREA 10.077000 ;
    PORT
      LAYER Metal2 ;
        RECT 94.360 215.060 94.760 215.460 ;
    END
  END S4END[0]
  PIN S4END[10]
    DIRECTION INPUT ;
    USE SIGNAL ;
    ANTENNAGATEAREA 0.180700 ;
    ANTENNADIFFAREA 2.015400 ;
    PORT
      LAYER Metal2 ;
        RECT 103.960 215.060 104.360 215.460 ;
    END
  END S4END[10]
  PIN S4END[11]
    DIRECTION INPUT ;
    USE SIGNAL ;
    ANTENNAGATEAREA 0.180700 ;
    ANTENNADIFFAREA 2.015400 ;
    PORT
      LAYER Metal2 ;
        RECT 104.920 215.060 105.320 215.460 ;
    END
  END S4END[11]
  PIN S4END[12]
    DIRECTION INPUT ;
    USE SIGNAL ;
    ANTENNAGATEAREA 0.180700 ;
    ANTENNADIFFAREA 2.015400 ;
    PORT
      LAYER Metal2 ;
        RECT 105.880 215.060 106.280 215.460 ;
    END
  END S4END[12]
  PIN S4END[13]
    DIRECTION INPUT ;
    USE SIGNAL ;
    ANTENNAGATEAREA 0.180700 ;
    ANTENNADIFFAREA 2.015400 ;
    PORT
      LAYER Metal2 ;
        RECT 106.840 215.060 107.240 215.460 ;
    END
  END S4END[13]
  PIN S4END[14]
    DIRECTION INPUT ;
    USE SIGNAL ;
    ANTENNAGATEAREA 0.180700 ;
    ANTENNADIFFAREA 2.015400 ;
    PORT
      LAYER Metal2 ;
        RECT 107.800 215.060 108.200 215.460 ;
    END
  END S4END[14]
  PIN S4END[15]
    DIRECTION INPUT ;
    USE SIGNAL ;
    ANTENNAGATEAREA 0.180700 ;
    ANTENNADIFFAREA 2.015400 ;
    PORT
      LAYER Metal2 ;
        RECT 108.760 215.060 109.160 215.460 ;
    END
  END S4END[15]
  PIN S4END[1]
    DIRECTION INPUT ;
    USE SIGNAL ;
    ANTENNAGATEAREA 1.066000 ;
    ANTENNADIFFAREA 10.077000 ;
    PORT
      LAYER Metal2 ;
        RECT 95.320 215.060 95.720 215.460 ;
    END
  END S4END[1]
  PIN S4END[2]
    DIRECTION INPUT ;
    USE SIGNAL ;
    ANTENNAGATEAREA 1.066000 ;
    ANTENNADIFFAREA 10.077000 ;
    PORT
      LAYER Metal2 ;
        RECT 96.280 215.060 96.680 215.460 ;
    END
  END S4END[2]
  PIN S4END[3]
    DIRECTION INPUT ;
    USE SIGNAL ;
    ANTENNAGATEAREA 1.066000 ;
    ANTENNADIFFAREA 10.077000 ;
    PORT
      LAYER Metal2 ;
        RECT 97.240 215.060 97.640 215.460 ;
    END
  END S4END[3]
  PIN S4END[4]
    DIRECTION INPUT ;
    USE SIGNAL ;
    ANTENNAGATEAREA 0.180700 ;
    ANTENNADIFFAREA 2.015400 ;
    PORT
      LAYER Metal2 ;
        RECT 98.200 215.060 98.600 215.460 ;
    END
  END S4END[4]
  PIN S4END[5]
    DIRECTION INPUT ;
    USE SIGNAL ;
    ANTENNAGATEAREA 0.180700 ;
    ANTENNADIFFAREA 2.015400 ;
    PORT
      LAYER Metal2 ;
        RECT 99.160 215.060 99.560 215.460 ;
    END
  END S4END[5]
  PIN S4END[6]
    DIRECTION INPUT ;
    USE SIGNAL ;
    ANTENNAGATEAREA 0.180700 ;
    ANTENNADIFFAREA 2.015400 ;
    PORT
      LAYER Metal2 ;
        RECT 100.120 215.060 100.520 215.460 ;
    END
  END S4END[6]
  PIN S4END[7]
    DIRECTION INPUT ;
    USE SIGNAL ;
    ANTENNAGATEAREA 0.180700 ;
    ANTENNADIFFAREA 2.015400 ;
    PORT
      LAYER Metal2 ;
        RECT 101.080 215.060 101.480 215.460 ;
    END
  END S4END[7]
  PIN S4END[8]
    DIRECTION INPUT ;
    USE SIGNAL ;
    ANTENNAGATEAREA 0.180700 ;
    ANTENNADIFFAREA 2.015400 ;
    PORT
      LAYER Metal2 ;
        RECT 102.040 215.060 102.440 215.460 ;
    END
  END S4END[8]
  PIN S4END[9]
    DIRECTION INPUT ;
    USE SIGNAL ;
    ANTENNAGATEAREA 0.180700 ;
    ANTENNADIFFAREA 2.015400 ;
    PORT
      LAYER Metal2 ;
        RECT 103.000 215.060 103.400 215.460 ;
    END
  END S4END[9]
  PIN UserCLK
    DIRECTION INPUT ;
    USE SIGNAL ;
    ANTENNAGATEAREA 1.450800 ;
    PORT
      LAYER Metal3 ;
        RECT 0.000 1.900 0.400 2.300 ;
    END
  END UserCLK
  PIN UserCLKo
    DIRECTION OUTPUT ;
    USE SIGNAL ;
    ANTENNADIFFAREA 2.724000 ;
    PORT
      LAYER Metal3 ;
        RECT 146.000 160.660 146.400 161.060 ;
    END
  END UserCLKo
  PIN VGND
    DIRECTION INOUT ;
    USE GROUND ;
    PORT
      LAYER Metal4 ;
        RECT 21.580 0.000 23.780 215.460 ;
    END
    PORT
      LAYER Metal4 ;
        RECT 97.180 0.000 99.380 215.460 ;
    END
  END VGND
  PIN VPWR
    DIRECTION INOUT ;
    USE POWER ;
    PORT
      LAYER Metal4 ;
        RECT 15.380 0.000 17.580 215.460 ;
    END
    PORT
      LAYER Metal4 ;
        RECT 90.980 0.000 93.180 215.460 ;
    END
  END VPWR
  PIN W1END[0]
    DIRECTION INPUT ;
    USE SIGNAL ;
    ANTENNAGATEAREA 1.524900 ;
    ANTENNADIFFAREA 14.107800 ;
    PORT
      LAYER Metal3 ;
        RECT 146.000 1.060 146.400 1.460 ;
    END
  END W1END[0]
  PIN W1END[1]
    DIRECTION INPUT ;
    USE SIGNAL ;
    ANTENNAGATEAREA 1.566500 ;
    ANTENNADIFFAREA 14.107800 ;
    PORT
      LAYER Metal3 ;
        RECT 146.000 2.740 146.400 3.140 ;
    END
  END W1END[1]
  PIN W1END[2]
    DIRECTION INPUT ;
    USE SIGNAL ;
    ANTENNAGATEAREA 1.524900 ;
    ANTENNADIFFAREA 14.107800 ;
    PORT
      LAYER Metal3 ;
        RECT 146.000 4.420 146.400 4.820 ;
    END
  END W1END[2]
  PIN W1END[3]
    DIRECTION INPUT ;
    USE SIGNAL ;
    ANTENNAGATEAREA 1.524900 ;
    ANTENNADIFFAREA 14.107800 ;
    PORT
      LAYER Metal3 ;
        RECT 146.000 6.100 146.400 6.500 ;
    END
  END W1END[3]
  PIN W2END[0]
    DIRECTION INPUT ;
    USE SIGNAL ;
    ANTENNAGATEAREA 0.668200 ;
    ANTENNADIFFAREA 6.046200 ;
    PORT
      LAYER Metal3 ;
        RECT 146.000 20.380 146.400 20.780 ;
    END
  END W2END[0]
  PIN W2END[1]
    DIRECTION INPUT ;
    USE SIGNAL ;
    ANTENNAGATEAREA 0.668200 ;
    ANTENNADIFFAREA 6.046200 ;
    PORT
      LAYER Metal3 ;
        RECT 146.000 22.060 146.400 22.460 ;
    END
  END W2END[1]
  PIN W2END[2]
    DIRECTION INPUT ;
    USE SIGNAL ;
    ANTENNAGATEAREA 0.668200 ;
    ANTENNADIFFAREA 6.046200 ;
    PORT
      LAYER Metal3 ;
        RECT 146.000 23.740 146.400 24.140 ;
    END
  END W2END[2]
  PIN W2END[3]
    DIRECTION INPUT ;
    USE SIGNAL ;
    ANTENNAGATEAREA 0.668200 ;
    ANTENNADIFFAREA 6.046200 ;
    PORT
      LAYER Metal3 ;
        RECT 146.000 25.420 146.400 25.820 ;
    END
  END W2END[3]
  PIN W2END[4]
    DIRECTION INPUT ;
    USE SIGNAL ;
    ANTENNAGATEAREA 0.668200 ;
    ANTENNADIFFAREA 6.046200 ;
    PORT
      LAYER Metal3 ;
        RECT 146.000 27.100 146.400 27.500 ;
    END
  END W2END[4]
  PIN W2END[5]
    DIRECTION INPUT ;
    USE SIGNAL ;
    ANTENNAGATEAREA 0.668200 ;
    ANTENNADIFFAREA 6.046200 ;
    PORT
      LAYER Metal3 ;
        RECT 146.000 28.780 146.400 29.180 ;
    END
  END W2END[5]
  PIN W2END[6]
    DIRECTION INPUT ;
    USE SIGNAL ;
    ANTENNAGATEAREA 0.668200 ;
    ANTENNADIFFAREA 6.046200 ;
    PORT
      LAYER Metal3 ;
        RECT 146.000 30.460 146.400 30.860 ;
    END
  END W2END[6]
  PIN W2END[7]
    DIRECTION INPUT ;
    USE SIGNAL ;
    ANTENNAGATEAREA 0.668200 ;
    ANTENNADIFFAREA 6.046200 ;
    PORT
      LAYER Metal3 ;
        RECT 146.000 32.140 146.400 32.540 ;
    END
  END W2END[7]
  PIN W2MID[0]
    DIRECTION INPUT ;
    USE SIGNAL ;
    ANTENNAGATEAREA 0.672100 ;
    ANTENNADIFFAREA 6.046200 ;
    PORT
      LAYER Metal3 ;
        RECT 146.000 10.300 146.400 10.700 ;
    END
  END W2MID[0]
  PIN W2MID[1]
    DIRECTION INPUT ;
    USE SIGNAL ;
    ANTENNAGATEAREA 0.672100 ;
    ANTENNADIFFAREA 6.046200 ;
    PORT
      LAYER Metal3 ;
        RECT 146.000 11.140 146.400 11.540 ;
    END
  END W2MID[1]
  PIN W2MID[2]
    DIRECTION INPUT ;
    USE SIGNAL ;
    ANTENNAGATEAREA 0.672100 ;
    ANTENNADIFFAREA 6.046200 ;
    PORT
      LAYER Metal3 ;
        RECT 146.000 11.980 146.400 12.380 ;
    END
  END W2MID[2]
  PIN W2MID[3]
    DIRECTION INPUT ;
    USE SIGNAL ;
    ANTENNAGATEAREA 0.672100 ;
    ANTENNADIFFAREA 6.046200 ;
    PORT
      LAYER Metal3 ;
        RECT 146.000 12.820 146.400 13.220 ;
    END
  END W2MID[3]
  PIN W2MID[4]
    DIRECTION INPUT ;
    USE SIGNAL ;
    ANTENNAGATEAREA 0.672100 ;
    ANTENNADIFFAREA 6.046200 ;
    PORT
      LAYER Metal3 ;
        RECT 146.000 13.660 146.400 14.060 ;
    END
  END W2MID[4]
  PIN W2MID[5]
    DIRECTION INPUT ;
    USE SIGNAL ;
    ANTENNAGATEAREA 0.672100 ;
    ANTENNADIFFAREA 6.046200 ;
    PORT
      LAYER Metal3 ;
        RECT 146.000 14.500 146.400 14.900 ;
    END
  END W2MID[5]
  PIN W2MID[6]
    DIRECTION INPUT ;
    USE SIGNAL ;
    ANTENNAGATEAREA 0.672100 ;
    ANTENNADIFFAREA 6.046200 ;
    PORT
      LAYER Metal3 ;
        RECT 146.000 15.340 146.400 15.740 ;
    END
  END W2MID[6]
  PIN W2MID[7]
    DIRECTION INPUT ;
    USE SIGNAL ;
    ANTENNAGATEAREA 0.672100 ;
    ANTENNADIFFAREA 6.046200 ;
    PORT
      LAYER Metal3 ;
        RECT 146.000 16.180 146.400 16.580 ;
    END
  END W2MID[7]
  PIN W6END[0]
    DIRECTION INPUT ;
    USE SIGNAL ;
    ANTENNAGATEAREA 0.668200 ;
    ANTENNADIFFAREA 6.046200 ;
    PORT
      LAYER Metal3 ;
        RECT 146.000 59.860 146.400 60.260 ;
    END
  END W6END[0]
  PIN W6END[10]
    DIRECTION INPUT ;
    USE SIGNAL ;
    ANTENNAGATEAREA 0.852800 ;
    ANTENNADIFFAREA 8.061600 ;
    PORT
      LAYER Metal3 ;
        RECT 146.000 76.660 146.400 77.060 ;
    END
  END W6END[10]
  PIN W6END[11]
    DIRECTION INPUT ;
    USE SIGNAL ;
    ANTENNAGATEAREA 0.820300 ;
    ANTENNADIFFAREA 8.061600 ;
    PORT
      LAYER Metal3 ;
        RECT 146.000 78.340 146.400 78.740 ;
    END
  END W6END[11]
  PIN W6END[1]
    DIRECTION INPUT ;
    USE SIGNAL ;
    ANTENNAGATEAREA 0.668200 ;
    ANTENNADIFFAREA 6.046200 ;
    PORT
      LAYER Metal3 ;
        RECT 146.000 61.540 146.400 61.940 ;
    END
  END W6END[1]
  PIN W6END[2]
    DIRECTION INPUT ;
    USE SIGNAL ;
    ANTENNAGATEAREA 0.668200 ;
    ANTENNADIFFAREA 6.046200 ;
    PORT
      LAYER Metal3 ;
        RECT 146.000 63.220 146.400 63.620 ;
    END
  END W6END[2]
  PIN W6END[3]
    DIRECTION INPUT ;
    USE SIGNAL ;
    ANTENNAGATEAREA 0.668200 ;
    ANTENNADIFFAREA 6.046200 ;
    PORT
      LAYER Metal3 ;
        RECT 146.000 64.900 146.400 65.300 ;
    END
  END W6END[3]
  PIN W6END[4]
    DIRECTION INPUT ;
    USE SIGNAL ;
    ANTENNAGATEAREA 0.852800 ;
    ANTENNADIFFAREA 8.061600 ;
    PORT
      LAYER Metal3 ;
        RECT 146.000 66.580 146.400 66.980 ;
    END
  END W6END[4]
  PIN W6END[5]
    DIRECTION INPUT ;
    USE SIGNAL ;
    ANTENNAGATEAREA 0.918600 ;
    ANTENNADIFFAREA 8.061600 ;
    PORT
      LAYER Metal3 ;
        RECT 146.000 68.260 146.400 68.660 ;
    END
  END W6END[5]
  PIN W6END[6]
    DIRECTION INPUT ;
    USE SIGNAL ;
    ANTENNAGATEAREA 0.852800 ;
    ANTENNADIFFAREA 8.061600 ;
    PORT
      LAYER Metal3 ;
        RECT 146.000 69.940 146.400 70.340 ;
    END
  END W6END[6]
  PIN W6END[7]
    DIRECTION INPUT ;
    USE SIGNAL ;
    ANTENNAGATEAREA 0.852800 ;
    ANTENNADIFFAREA 8.061600 ;
    PORT
      LAYER Metal3 ;
        RECT 146.000 71.620 146.400 72.020 ;
    END
  END W6END[7]
  PIN W6END[8]
    DIRECTION INPUT ;
    USE SIGNAL ;
    ANTENNAGATEAREA 0.852800 ;
    ANTENNADIFFAREA 8.061600 ;
    PORT
      LAYER Metal3 ;
        RECT 146.000 73.300 146.400 73.700 ;
    END
  END W6END[8]
  PIN W6END[9]
    DIRECTION INPUT ;
    USE SIGNAL ;
    ANTENNAGATEAREA 0.881400 ;
    ANTENNADIFFAREA 8.061600 ;
    PORT
      LAYER Metal3 ;
        RECT 146.000 74.980 146.400 75.380 ;
    END
  END W6END[9]
  PIN WW4END[0]
    DIRECTION INPUT ;
    USE SIGNAL ;
    ANTENNAGATEAREA 0.639600 ;
    ANTENNADIFFAREA 6.046200 ;
    PORT
      LAYER Metal3 ;
        RECT 146.000 39.700 146.400 40.100 ;
    END
  END WW4END[0]
  PIN WW4END[10]
    DIRECTION INPUT ;
    USE SIGNAL ;
    ANTENNAGATEAREA 0.426400 ;
    ANTENNADIFFAREA 4.030800 ;
    PORT
      LAYER Metal3 ;
        RECT 146.000 48.100 146.400 48.500 ;
    END
  END WW4END[10]
  PIN WW4END[11]
    DIRECTION INPUT ;
    USE SIGNAL ;
    ANTENNAGATEAREA 0.426400 ;
    ANTENNADIFFAREA 4.030800 ;
    PORT
      LAYER Metal3 ;
        RECT 146.000 48.940 146.400 49.340 ;
    END
  END WW4END[11]
  PIN WW4END[12]
    DIRECTION INPUT ;
    USE SIGNAL ;
    ANTENNAGATEAREA 0.639600 ;
    ANTENNADIFFAREA 6.046200 ;
    PORT
      LAYER Metal3 ;
        RECT 146.000 49.780 146.400 50.180 ;
    END
  END WW4END[12]
  PIN WW4END[13]
    DIRECTION INPUT ;
    USE SIGNAL ;
    ANTENNAGATEAREA 0.705400 ;
    ANTENNADIFFAREA 6.046200 ;
    PORT
      LAYER Metal3 ;
        RECT 146.000 50.620 146.400 51.020 ;
    END
  END WW4END[13]
  PIN WW4END[14]
    DIRECTION INPUT ;
    USE SIGNAL ;
    ANTENNAGATEAREA 0.639600 ;
    ANTENNADIFFAREA 6.046200 ;
    PORT
      LAYER Metal3 ;
        RECT 146.000 51.460 146.400 51.860 ;
    END
  END WW4END[14]
  PIN WW4END[15]
    DIRECTION INPUT ;
    USE SIGNAL ;
    ANTENNAGATEAREA 0.639600 ;
    ANTENNADIFFAREA 6.046200 ;
    PORT
      LAYER Metal3 ;
        RECT 146.000 52.300 146.400 52.700 ;
    END
  END WW4END[15]
  PIN WW4END[1]
    DIRECTION INPUT ;
    USE SIGNAL ;
    ANTENNAGATEAREA 0.705400 ;
    ANTENNADIFFAREA 6.046200 ;
    PORT
      LAYER Metal3 ;
        RECT 146.000 40.540 146.400 40.940 ;
    END
  END WW4END[1]
  PIN WW4END[2]
    DIRECTION INPUT ;
    USE SIGNAL ;
    ANTENNAGATEAREA 0.639600 ;
    ANTENNADIFFAREA 6.046200 ;
    PORT
      LAYER Metal3 ;
        RECT 146.000 41.380 146.400 41.780 ;
    END
  END WW4END[2]
  PIN WW4END[3]
    DIRECTION INPUT ;
    USE SIGNAL ;
    ANTENNAGATEAREA 0.639600 ;
    ANTENNADIFFAREA 6.046200 ;
    PORT
      LAYER Metal3 ;
        RECT 146.000 42.220 146.400 42.620 ;
    END
  END WW4END[3]
  PIN WW4END[4]
    DIRECTION INPUT ;
    USE SIGNAL ;
    ANTENNAGATEAREA 0.426400 ;
    ANTENNADIFFAREA 4.030800 ;
    PORT
      LAYER Metal3 ;
        RECT 146.000 43.060 146.400 43.460 ;
    END
  END WW4END[4]
  PIN WW4END[5]
    DIRECTION INPUT ;
    USE SIGNAL ;
    ANTENNAGATEAREA 0.426400 ;
    ANTENNADIFFAREA 4.030800 ;
    PORT
      LAYER Metal3 ;
        RECT 146.000 43.900 146.400 44.300 ;
    END
  END WW4END[5]
  PIN WW4END[6]
    DIRECTION INPUT ;
    USE SIGNAL ;
    ANTENNAGATEAREA 0.426400 ;
    ANTENNADIFFAREA 4.030800 ;
    PORT
      LAYER Metal3 ;
        RECT 146.000 44.740 146.400 45.140 ;
    END
  END WW4END[6]
  PIN WW4END[7]
    DIRECTION INPUT ;
    USE SIGNAL ;
    ANTENNAGATEAREA 0.426400 ;
    ANTENNADIFFAREA 4.030800 ;
    PORT
      LAYER Metal3 ;
        RECT 146.000 45.580 146.400 45.980 ;
    END
  END WW4END[7]
  PIN WW4END[8]
    DIRECTION INPUT ;
    USE SIGNAL ;
    ANTENNAGATEAREA 0.426400 ;
    ANTENNADIFFAREA 4.030800 ;
    PORT
      LAYER Metal3 ;
        RECT 146.000 46.420 146.400 46.820 ;
    END
  END WW4END[8]
  PIN WW4END[9]
    DIRECTION INPUT ;
    USE SIGNAL ;
    ANTENNAGATEAREA 0.426400 ;
    ANTENNADIFFAREA 4.030800 ;
    PORT
      LAYER Metal3 ;
        RECT 146.000 47.260 146.400 47.660 ;
    END
  END WW4END[9]
  OBS
      LAYER GatPoly ;
        RECT 2.880 3.630 143.520 211.830 ;
      LAYER Metal1 ;
        RECT 2.880 3.560 143.520 211.900 ;
      LAYER Metal2 ;
        RECT 0.375 214.850 1.990 215.185 ;
        RECT 2.810 214.850 2.950 215.185 ;
        RECT 3.770 214.850 3.910 215.185 ;
        RECT 4.730 214.850 4.870 215.185 ;
        RECT 5.690 214.850 9.670 215.185 ;
        RECT 10.490 214.850 10.630 215.185 ;
        RECT 11.450 214.850 11.590 215.185 ;
        RECT 12.410 214.850 12.550 215.185 ;
        RECT 13.370 214.850 13.510 215.185 ;
        RECT 14.330 214.850 14.470 215.185 ;
        RECT 15.290 214.850 15.430 215.185 ;
        RECT 16.250 214.850 16.390 215.185 ;
        RECT 17.210 214.850 22.150 215.185 ;
        RECT 22.970 214.850 23.110 215.185 ;
        RECT 23.930 214.850 24.070 215.185 ;
        RECT 24.890 214.850 25.030 215.185 ;
        RECT 25.850 214.850 25.990 215.185 ;
        RECT 26.810 214.850 26.950 215.185 ;
        RECT 27.770 214.850 27.910 215.185 ;
        RECT 28.730 214.850 28.870 215.185 ;
        RECT 29.690 214.850 37.510 215.185 ;
        RECT 38.330 214.850 38.470 215.185 ;
        RECT 39.290 214.850 39.430 215.185 ;
        RECT 40.250 214.850 40.390 215.185 ;
        RECT 41.210 214.850 41.350 215.185 ;
        RECT 42.170 214.850 42.310 215.185 ;
        RECT 43.130 214.850 43.270 215.185 ;
        RECT 44.090 214.850 44.230 215.185 ;
        RECT 45.050 214.850 45.190 215.185 ;
        RECT 46.010 214.850 46.150 215.185 ;
        RECT 46.970 214.850 47.110 215.185 ;
        RECT 47.930 214.850 48.070 215.185 ;
        RECT 48.890 214.850 49.030 215.185 ;
        RECT 49.850 214.850 49.990 215.185 ;
        RECT 50.810 214.850 50.950 215.185 ;
        RECT 51.770 214.850 51.910 215.185 ;
        RECT 52.730 214.850 58.630 215.185 ;
        RECT 59.450 214.850 59.590 215.185 ;
        RECT 60.410 214.850 60.550 215.185 ;
        RECT 61.370 214.850 61.510 215.185 ;
        RECT 62.330 214.850 66.310 215.185 ;
        RECT 67.130 214.850 67.270 215.185 ;
        RECT 68.090 214.850 68.230 215.185 ;
        RECT 69.050 214.850 69.190 215.185 ;
        RECT 70.010 214.850 70.150 215.185 ;
        RECT 70.970 214.850 71.110 215.185 ;
        RECT 71.930 214.850 72.070 215.185 ;
        RECT 72.890 214.850 73.030 215.185 ;
        RECT 73.850 214.850 78.790 215.185 ;
        RECT 79.610 214.850 79.750 215.185 ;
        RECT 80.570 214.850 80.710 215.185 ;
        RECT 81.530 214.850 81.670 215.185 ;
        RECT 82.490 214.850 82.630 215.185 ;
        RECT 83.450 214.850 83.590 215.185 ;
        RECT 84.410 214.850 84.550 215.185 ;
        RECT 85.370 214.850 85.510 215.185 ;
        RECT 86.330 214.850 94.150 215.185 ;
        RECT 94.970 214.850 95.110 215.185 ;
        RECT 95.930 214.850 96.070 215.185 ;
        RECT 96.890 214.850 97.030 215.185 ;
        RECT 97.850 214.850 97.990 215.185 ;
        RECT 98.810 214.850 98.950 215.185 ;
        RECT 99.770 214.850 99.910 215.185 ;
        RECT 100.730 214.850 100.870 215.185 ;
        RECT 101.690 214.850 101.830 215.185 ;
        RECT 102.650 214.850 102.790 215.185 ;
        RECT 103.610 214.850 103.750 215.185 ;
        RECT 104.570 214.850 104.710 215.185 ;
        RECT 105.530 214.850 105.670 215.185 ;
        RECT 106.490 214.850 106.630 215.185 ;
        RECT 107.450 214.850 107.590 215.185 ;
        RECT 108.410 214.850 108.550 215.185 ;
        RECT 109.370 214.850 121.030 215.185 ;
        RECT 121.850 214.850 121.990 215.185 ;
        RECT 122.810 214.850 122.950 215.185 ;
        RECT 123.770 214.850 123.910 215.185 ;
        RECT 124.730 214.850 124.870 215.185 ;
        RECT 125.690 214.850 125.830 215.185 ;
        RECT 126.650 214.850 126.790 215.185 ;
        RECT 127.610 214.850 127.750 215.185 ;
        RECT 128.570 214.850 128.710 215.185 ;
        RECT 129.530 214.850 129.670 215.185 ;
        RECT 130.490 214.850 130.630 215.185 ;
        RECT 131.450 214.850 131.590 215.185 ;
        RECT 132.410 214.850 132.550 215.185 ;
        RECT 133.370 214.850 133.510 215.185 ;
        RECT 134.330 214.850 134.470 215.185 ;
        RECT 135.290 214.850 135.430 215.185 ;
        RECT 136.250 214.850 136.390 215.185 ;
        RECT 137.210 214.850 137.350 215.185 ;
        RECT 138.170 214.850 138.310 215.185 ;
        RECT 139.130 214.850 139.270 215.185 ;
        RECT 140.090 214.850 146.025 215.185 ;
        RECT 0.375 0.610 146.025 214.850 ;
        RECT 0.375 0.275 1.990 0.610 ;
        RECT 2.810 0.275 2.950 0.610 ;
        RECT 3.770 0.275 3.910 0.610 ;
        RECT 4.730 0.275 4.870 0.610 ;
        RECT 5.690 0.275 9.670 0.610 ;
        RECT 10.490 0.275 10.630 0.610 ;
        RECT 11.450 0.275 11.590 0.610 ;
        RECT 12.410 0.275 12.550 0.610 ;
        RECT 13.370 0.275 13.510 0.610 ;
        RECT 14.330 0.275 14.470 0.610 ;
        RECT 15.290 0.275 15.430 0.610 ;
        RECT 16.250 0.275 16.390 0.610 ;
        RECT 17.210 0.275 22.150 0.610 ;
        RECT 22.970 0.275 23.110 0.610 ;
        RECT 23.930 0.275 24.070 0.610 ;
        RECT 24.890 0.275 25.030 0.610 ;
        RECT 25.850 0.275 25.990 0.610 ;
        RECT 26.810 0.275 26.950 0.610 ;
        RECT 27.770 0.275 27.910 0.610 ;
        RECT 28.730 0.275 28.870 0.610 ;
        RECT 29.690 0.275 37.510 0.610 ;
        RECT 38.330 0.275 38.470 0.610 ;
        RECT 39.290 0.275 39.430 0.610 ;
        RECT 40.250 0.275 40.390 0.610 ;
        RECT 41.210 0.275 41.350 0.610 ;
        RECT 42.170 0.275 42.310 0.610 ;
        RECT 43.130 0.275 43.270 0.610 ;
        RECT 44.090 0.275 44.230 0.610 ;
        RECT 45.050 0.275 45.190 0.610 ;
        RECT 46.010 0.275 46.150 0.610 ;
        RECT 46.970 0.275 47.110 0.610 ;
        RECT 47.930 0.275 48.070 0.610 ;
        RECT 48.890 0.275 49.030 0.610 ;
        RECT 49.850 0.275 49.990 0.610 ;
        RECT 50.810 0.275 50.950 0.610 ;
        RECT 51.770 0.275 51.910 0.610 ;
        RECT 52.730 0.275 58.630 0.610 ;
        RECT 59.450 0.275 59.590 0.610 ;
        RECT 60.410 0.275 60.550 0.610 ;
        RECT 61.370 0.275 61.510 0.610 ;
        RECT 62.330 0.275 66.310 0.610 ;
        RECT 67.130 0.275 67.270 0.610 ;
        RECT 68.090 0.275 68.230 0.610 ;
        RECT 69.050 0.275 69.190 0.610 ;
        RECT 70.010 0.275 70.150 0.610 ;
        RECT 70.970 0.275 71.110 0.610 ;
        RECT 71.930 0.275 72.070 0.610 ;
        RECT 72.890 0.275 73.030 0.610 ;
        RECT 73.850 0.275 78.790 0.610 ;
        RECT 79.610 0.275 79.750 0.610 ;
        RECT 80.570 0.275 80.710 0.610 ;
        RECT 81.530 0.275 81.670 0.610 ;
        RECT 82.490 0.275 82.630 0.610 ;
        RECT 83.450 0.275 83.590 0.610 ;
        RECT 84.410 0.275 84.550 0.610 ;
        RECT 85.370 0.275 85.510 0.610 ;
        RECT 86.330 0.275 94.150 0.610 ;
        RECT 94.970 0.275 95.110 0.610 ;
        RECT 95.930 0.275 96.070 0.610 ;
        RECT 96.890 0.275 97.030 0.610 ;
        RECT 97.850 0.275 97.990 0.610 ;
        RECT 98.810 0.275 98.950 0.610 ;
        RECT 99.770 0.275 99.910 0.610 ;
        RECT 100.730 0.275 100.870 0.610 ;
        RECT 101.690 0.275 101.830 0.610 ;
        RECT 102.650 0.275 102.790 0.610 ;
        RECT 103.610 0.275 103.750 0.610 ;
        RECT 104.570 0.275 104.710 0.610 ;
        RECT 105.530 0.275 105.670 0.610 ;
        RECT 106.490 0.275 106.630 0.610 ;
        RECT 107.450 0.275 107.590 0.610 ;
        RECT 108.410 0.275 108.550 0.610 ;
        RECT 109.370 0.275 121.030 0.610 ;
        RECT 121.850 0.275 121.990 0.610 ;
        RECT 122.810 0.275 122.950 0.610 ;
        RECT 123.770 0.275 123.910 0.610 ;
        RECT 124.730 0.275 124.870 0.610 ;
        RECT 125.690 0.275 125.830 0.610 ;
        RECT 126.650 0.275 126.790 0.610 ;
        RECT 127.610 0.275 127.750 0.610 ;
        RECT 128.570 0.275 128.710 0.610 ;
        RECT 129.530 0.275 129.670 0.610 ;
        RECT 130.490 0.275 130.630 0.610 ;
        RECT 131.450 0.275 131.590 0.610 ;
        RECT 132.410 0.275 132.550 0.610 ;
        RECT 133.370 0.275 133.510 0.610 ;
        RECT 134.330 0.275 134.470 0.610 ;
        RECT 135.290 0.275 135.430 0.610 ;
        RECT 136.250 0.275 136.390 0.610 ;
        RECT 137.210 0.275 137.350 0.610 ;
        RECT 138.170 0.275 138.310 0.610 ;
        RECT 139.130 0.275 139.270 0.610 ;
        RECT 140.090 0.275 146.025 0.610 ;
      LAYER Metal3 ;
        RECT 0.335 215.030 146.065 215.145 ;
        RECT 0.335 214.210 145.790 215.030 ;
        RECT 0.335 214.190 146.065 214.210 ;
        RECT 0.610 213.370 146.065 214.190 ;
        RECT 0.335 213.350 146.065 213.370 ;
        RECT 0.335 212.530 145.790 213.350 ;
        RECT 0.335 211.670 146.065 212.530 ;
        RECT 0.610 210.850 145.790 211.670 ;
        RECT 0.335 209.990 146.065 210.850 ;
        RECT 0.335 209.170 145.790 209.990 ;
        RECT 0.335 209.150 146.065 209.170 ;
        RECT 0.610 208.330 146.065 209.150 ;
        RECT 0.335 208.310 146.065 208.330 ;
        RECT 0.335 207.490 145.790 208.310 ;
        RECT 0.335 206.630 146.065 207.490 ;
        RECT 0.610 205.810 145.790 206.630 ;
        RECT 0.335 204.950 146.065 205.810 ;
        RECT 0.335 204.130 145.790 204.950 ;
        RECT 0.335 203.270 146.065 204.130 ;
        RECT 0.610 202.450 145.790 203.270 ;
        RECT 0.335 201.590 146.065 202.450 ;
        RECT 0.335 200.770 145.790 201.590 ;
        RECT 0.335 200.750 146.065 200.770 ;
        RECT 0.610 199.930 146.065 200.750 ;
        RECT 0.335 199.910 146.065 199.930 ;
        RECT 0.335 199.090 145.790 199.910 ;
        RECT 0.335 198.230 146.065 199.090 ;
        RECT 0.610 197.410 145.790 198.230 ;
        RECT 0.335 196.550 146.065 197.410 ;
        RECT 0.335 195.730 145.790 196.550 ;
        RECT 0.335 195.710 146.065 195.730 ;
        RECT 0.610 194.890 146.065 195.710 ;
        RECT 0.335 194.870 146.065 194.890 ;
        RECT 0.335 194.050 145.790 194.870 ;
        RECT 0.335 193.190 146.065 194.050 ;
        RECT 0.335 192.370 145.790 193.190 ;
        RECT 0.335 192.350 146.065 192.370 ;
        RECT 0.610 191.530 146.065 192.350 ;
        RECT 0.335 191.510 146.065 191.530 ;
        RECT 0.335 190.690 145.790 191.510 ;
        RECT 0.335 189.830 146.065 190.690 ;
        RECT 0.610 189.010 145.790 189.830 ;
        RECT 0.335 188.150 146.065 189.010 ;
        RECT 0.335 187.330 145.790 188.150 ;
        RECT 0.335 187.310 146.065 187.330 ;
        RECT 0.610 186.490 146.065 187.310 ;
        RECT 0.335 186.470 146.065 186.490 ;
        RECT 0.335 185.650 145.790 186.470 ;
        RECT 0.335 184.790 146.065 185.650 ;
        RECT 0.610 183.970 145.790 184.790 ;
        RECT 0.335 183.110 146.065 183.970 ;
        RECT 0.335 182.290 145.790 183.110 ;
        RECT 0.335 181.430 146.065 182.290 ;
        RECT 0.610 180.610 145.790 181.430 ;
        RECT 0.335 179.750 146.065 180.610 ;
        RECT 0.335 178.930 145.790 179.750 ;
        RECT 0.335 178.910 146.065 178.930 ;
        RECT 0.610 178.090 146.065 178.910 ;
        RECT 0.335 178.070 146.065 178.090 ;
        RECT 0.335 177.250 145.790 178.070 ;
        RECT 0.335 176.390 146.065 177.250 ;
        RECT 0.610 175.570 145.790 176.390 ;
        RECT 0.335 174.710 146.065 175.570 ;
        RECT 0.335 173.890 145.790 174.710 ;
        RECT 0.335 173.870 146.065 173.890 ;
        RECT 0.610 173.050 146.065 173.870 ;
        RECT 0.335 173.030 146.065 173.050 ;
        RECT 0.335 172.210 145.790 173.030 ;
        RECT 0.335 171.350 146.065 172.210 ;
        RECT 0.335 170.530 145.790 171.350 ;
        RECT 0.335 170.510 146.065 170.530 ;
        RECT 0.610 169.690 146.065 170.510 ;
        RECT 0.335 169.670 146.065 169.690 ;
        RECT 0.335 168.850 145.790 169.670 ;
        RECT 0.335 167.990 146.065 168.850 ;
        RECT 0.610 167.170 145.790 167.990 ;
        RECT 0.335 166.310 146.065 167.170 ;
        RECT 0.335 165.490 145.790 166.310 ;
        RECT 0.335 165.470 146.065 165.490 ;
        RECT 0.610 164.650 146.065 165.470 ;
        RECT 0.335 164.630 146.065 164.650 ;
        RECT 0.335 163.810 145.790 164.630 ;
        RECT 0.335 162.950 146.065 163.810 ;
        RECT 0.610 162.130 145.790 162.950 ;
        RECT 0.335 161.270 146.065 162.130 ;
        RECT 0.335 160.450 145.790 161.270 ;
        RECT 0.335 160.430 146.065 160.450 ;
        RECT 0.610 159.610 146.065 160.430 ;
        RECT 0.335 159.590 146.065 159.610 ;
        RECT 0.335 158.770 145.790 159.590 ;
        RECT 0.335 157.910 146.065 158.770 ;
        RECT 0.610 157.090 145.790 157.910 ;
        RECT 0.335 156.230 146.065 157.090 ;
        RECT 0.335 155.410 145.790 156.230 ;
        RECT 0.335 155.390 146.065 155.410 ;
        RECT 0.610 154.570 146.065 155.390 ;
        RECT 0.335 154.550 146.065 154.570 ;
        RECT 0.335 153.730 145.790 154.550 ;
        RECT 0.335 152.870 146.065 153.730 ;
        RECT 0.610 152.050 145.790 152.870 ;
        RECT 0.335 151.190 146.065 152.050 ;
        RECT 0.335 150.370 145.790 151.190 ;
        RECT 0.335 149.510 146.065 150.370 ;
        RECT 0.610 148.690 145.790 149.510 ;
        RECT 0.335 147.830 146.065 148.690 ;
        RECT 0.335 147.010 145.790 147.830 ;
        RECT 0.335 146.990 146.065 147.010 ;
        RECT 0.610 146.170 146.065 146.990 ;
        RECT 0.335 146.150 146.065 146.170 ;
        RECT 0.335 145.330 145.790 146.150 ;
        RECT 0.335 144.470 146.065 145.330 ;
        RECT 0.610 143.650 145.790 144.470 ;
        RECT 0.335 142.790 146.065 143.650 ;
        RECT 0.335 141.970 145.790 142.790 ;
        RECT 0.335 141.950 146.065 141.970 ;
        RECT 0.610 141.130 146.065 141.950 ;
        RECT 0.335 141.110 146.065 141.130 ;
        RECT 0.335 140.290 145.790 141.110 ;
        RECT 0.335 139.430 146.065 140.290 ;
        RECT 0.610 138.610 145.790 139.430 ;
        RECT 0.335 137.750 146.065 138.610 ;
        RECT 0.335 136.930 145.790 137.750 ;
        RECT 0.335 136.910 146.065 136.930 ;
        RECT 0.610 136.090 146.065 136.910 ;
        RECT 0.335 136.070 146.065 136.090 ;
        RECT 0.335 135.250 145.790 136.070 ;
        RECT 0.335 134.390 146.065 135.250 ;
        RECT 0.610 133.570 145.790 134.390 ;
        RECT 0.335 132.710 146.065 133.570 ;
        RECT 0.335 131.890 145.790 132.710 ;
        RECT 0.335 131.870 146.065 131.890 ;
        RECT 0.610 131.050 146.065 131.870 ;
        RECT 0.335 131.030 146.065 131.050 ;
        RECT 0.335 130.210 145.790 131.030 ;
        RECT 0.335 129.350 146.065 130.210 ;
        RECT 0.335 128.530 145.790 129.350 ;
        RECT 0.335 128.510 146.065 128.530 ;
        RECT 0.610 127.690 146.065 128.510 ;
        RECT 0.335 127.670 146.065 127.690 ;
        RECT 0.335 126.850 145.790 127.670 ;
        RECT 0.335 125.990 146.065 126.850 ;
        RECT 0.610 125.170 145.790 125.990 ;
        RECT 0.335 124.310 146.065 125.170 ;
        RECT 0.335 123.490 145.790 124.310 ;
        RECT 0.335 123.470 146.065 123.490 ;
        RECT 0.610 122.650 146.065 123.470 ;
        RECT 0.335 122.630 146.065 122.650 ;
        RECT 0.335 121.810 145.790 122.630 ;
        RECT 0.335 120.950 146.065 121.810 ;
        RECT 0.610 120.130 145.790 120.950 ;
        RECT 0.335 119.270 146.065 120.130 ;
        RECT 0.335 118.450 145.790 119.270 ;
        RECT 0.335 118.430 146.065 118.450 ;
        RECT 0.610 117.610 146.065 118.430 ;
        RECT 0.335 117.590 146.065 117.610 ;
        RECT 0.335 116.770 145.790 117.590 ;
        RECT 0.335 115.910 146.065 116.770 ;
        RECT 0.610 115.090 145.790 115.910 ;
        RECT 0.335 114.230 146.065 115.090 ;
        RECT 0.335 113.410 145.790 114.230 ;
        RECT 0.335 113.390 146.065 113.410 ;
        RECT 0.610 112.570 146.065 113.390 ;
        RECT 0.335 112.550 146.065 112.570 ;
        RECT 0.335 111.730 145.790 112.550 ;
        RECT 0.335 110.870 146.065 111.730 ;
        RECT 0.610 110.050 145.790 110.870 ;
        RECT 0.335 109.190 146.065 110.050 ;
        RECT 0.335 108.370 145.790 109.190 ;
        RECT 0.335 107.510 146.065 108.370 ;
        RECT 0.610 106.690 145.790 107.510 ;
        RECT 0.335 105.830 146.065 106.690 ;
        RECT 0.335 105.010 145.790 105.830 ;
        RECT 0.335 104.990 146.065 105.010 ;
        RECT 0.610 104.170 146.065 104.990 ;
        RECT 0.335 104.150 146.065 104.170 ;
        RECT 0.335 103.330 145.790 104.150 ;
        RECT 0.335 102.470 146.065 103.330 ;
        RECT 0.610 101.650 145.790 102.470 ;
        RECT 0.335 100.790 146.065 101.650 ;
        RECT 0.335 99.970 145.790 100.790 ;
        RECT 0.335 99.950 146.065 99.970 ;
        RECT 0.610 99.130 146.065 99.950 ;
        RECT 0.335 99.110 146.065 99.130 ;
        RECT 0.335 98.290 145.790 99.110 ;
        RECT 0.335 97.430 146.065 98.290 ;
        RECT 0.610 96.610 145.790 97.430 ;
        RECT 0.335 95.750 146.065 96.610 ;
        RECT 0.335 94.930 145.790 95.750 ;
        RECT 0.335 94.910 146.065 94.930 ;
        RECT 0.610 94.090 146.065 94.910 ;
        RECT 0.335 94.070 146.065 94.090 ;
        RECT 0.335 93.250 145.790 94.070 ;
        RECT 0.335 92.390 146.065 93.250 ;
        RECT 0.610 91.570 145.790 92.390 ;
        RECT 0.335 90.710 146.065 91.570 ;
        RECT 0.335 89.890 145.790 90.710 ;
        RECT 0.335 89.870 146.065 89.890 ;
        RECT 0.610 89.050 146.065 89.870 ;
        RECT 0.335 89.030 146.065 89.050 ;
        RECT 0.335 88.210 145.790 89.030 ;
        RECT 0.335 87.350 146.065 88.210 ;
        RECT 0.335 86.530 145.790 87.350 ;
        RECT 0.335 85.670 146.065 86.530 ;
        RECT 0.335 84.850 145.790 85.670 ;
        RECT 0.335 84.830 146.065 84.850 ;
        RECT 0.610 84.010 146.065 84.830 ;
        RECT 0.335 83.990 146.065 84.010 ;
        RECT 0.335 83.170 145.790 83.990 ;
        RECT 0.335 82.310 146.065 83.170 ;
        RECT 0.610 81.490 145.790 82.310 ;
        RECT 0.335 80.630 146.065 81.490 ;
        RECT 0.335 79.810 145.790 80.630 ;
        RECT 0.335 79.790 146.065 79.810 ;
        RECT 0.610 78.970 146.065 79.790 ;
        RECT 0.335 78.950 146.065 78.970 ;
        RECT 0.335 78.130 145.790 78.950 ;
        RECT 0.335 77.270 146.065 78.130 ;
        RECT 0.610 76.450 145.790 77.270 ;
        RECT 0.335 75.590 146.065 76.450 ;
        RECT 0.335 74.770 145.790 75.590 ;
        RECT 0.335 74.750 146.065 74.770 ;
        RECT 0.610 73.930 146.065 74.750 ;
        RECT 0.335 73.910 146.065 73.930 ;
        RECT 0.335 73.090 145.790 73.910 ;
        RECT 0.335 72.230 146.065 73.090 ;
        RECT 0.610 71.410 145.790 72.230 ;
        RECT 0.335 70.550 146.065 71.410 ;
        RECT 0.335 69.730 145.790 70.550 ;
        RECT 0.335 69.710 146.065 69.730 ;
        RECT 0.610 68.890 146.065 69.710 ;
        RECT 0.335 68.870 146.065 68.890 ;
        RECT 0.335 68.050 145.790 68.870 ;
        RECT 0.335 67.190 146.065 68.050 ;
        RECT 0.610 66.370 145.790 67.190 ;
        RECT 0.335 65.510 146.065 66.370 ;
        RECT 0.335 64.690 145.790 65.510 ;
        RECT 0.335 64.670 146.065 64.690 ;
        RECT 0.610 63.850 146.065 64.670 ;
        RECT 0.335 63.830 146.065 63.850 ;
        RECT 0.335 63.010 145.790 63.830 ;
        RECT 0.335 62.150 146.065 63.010 ;
        RECT 0.610 61.330 145.790 62.150 ;
        RECT 0.335 60.470 146.065 61.330 ;
        RECT 0.335 59.650 145.790 60.470 ;
        RECT 0.335 59.630 146.065 59.650 ;
        RECT 0.610 58.810 146.065 59.630 ;
        RECT 0.335 57.110 146.065 58.810 ;
        RECT 0.610 56.290 146.065 57.110 ;
        RECT 0.335 54.590 146.065 56.290 ;
        RECT 0.610 53.770 146.065 54.590 ;
        RECT 0.335 52.910 146.065 53.770 ;
        RECT 0.335 52.090 145.790 52.910 ;
        RECT 0.335 52.070 146.065 52.090 ;
        RECT 0.610 51.250 145.790 52.070 ;
        RECT 0.335 51.230 146.065 51.250 ;
        RECT 0.335 50.410 145.790 51.230 ;
        RECT 0.335 50.390 146.065 50.410 ;
        RECT 0.335 49.570 145.790 50.390 ;
        RECT 0.335 49.550 146.065 49.570 ;
        RECT 0.610 48.730 145.790 49.550 ;
        RECT 0.335 48.710 146.065 48.730 ;
        RECT 0.335 47.890 145.790 48.710 ;
        RECT 0.335 47.870 146.065 47.890 ;
        RECT 0.335 47.050 145.790 47.870 ;
        RECT 0.335 47.030 146.065 47.050 ;
        RECT 0.610 46.210 145.790 47.030 ;
        RECT 0.335 46.190 146.065 46.210 ;
        RECT 0.335 45.370 145.790 46.190 ;
        RECT 0.335 45.350 146.065 45.370 ;
        RECT 0.335 44.530 145.790 45.350 ;
        RECT 0.335 44.510 146.065 44.530 ;
        RECT 0.610 43.690 145.790 44.510 ;
        RECT 0.335 43.670 146.065 43.690 ;
        RECT 0.335 42.850 145.790 43.670 ;
        RECT 0.335 42.830 146.065 42.850 ;
        RECT 0.335 42.010 145.790 42.830 ;
        RECT 0.335 41.990 146.065 42.010 ;
        RECT 0.610 41.170 145.790 41.990 ;
        RECT 0.335 41.150 146.065 41.170 ;
        RECT 0.335 40.330 145.790 41.150 ;
        RECT 0.335 40.310 146.065 40.330 ;
        RECT 0.335 39.490 145.790 40.310 ;
        RECT 0.335 39.470 146.065 39.490 ;
        RECT 0.610 38.650 146.065 39.470 ;
        RECT 0.335 36.950 146.065 38.650 ;
        RECT 0.610 36.130 146.065 36.950 ;
        RECT 0.335 34.430 146.065 36.130 ;
        RECT 0.610 33.610 146.065 34.430 ;
        RECT 0.335 32.750 146.065 33.610 ;
        RECT 0.335 31.930 145.790 32.750 ;
        RECT 0.335 31.910 146.065 31.930 ;
        RECT 0.610 31.090 146.065 31.910 ;
        RECT 0.335 31.070 146.065 31.090 ;
        RECT 0.335 30.250 145.790 31.070 ;
        RECT 0.335 29.390 146.065 30.250 ;
        RECT 0.610 28.570 145.790 29.390 ;
        RECT 0.335 27.710 146.065 28.570 ;
        RECT 0.335 26.890 145.790 27.710 ;
        RECT 0.335 26.870 146.065 26.890 ;
        RECT 0.610 26.050 146.065 26.870 ;
        RECT 0.335 26.030 146.065 26.050 ;
        RECT 0.335 25.210 145.790 26.030 ;
        RECT 0.335 24.350 146.065 25.210 ;
        RECT 0.610 23.530 145.790 24.350 ;
        RECT 0.335 22.670 146.065 23.530 ;
        RECT 0.335 21.850 145.790 22.670 ;
        RECT 0.335 21.830 146.065 21.850 ;
        RECT 0.610 21.010 146.065 21.830 ;
        RECT 0.335 20.990 146.065 21.010 ;
        RECT 0.335 20.170 145.790 20.990 ;
        RECT 0.335 19.310 146.065 20.170 ;
        RECT 0.610 18.490 146.065 19.310 ;
        RECT 0.335 16.790 146.065 18.490 ;
        RECT 0.610 15.970 145.790 16.790 ;
        RECT 0.335 15.950 146.065 15.970 ;
        RECT 0.335 15.130 145.790 15.950 ;
        RECT 0.335 15.110 146.065 15.130 ;
        RECT 0.335 14.290 145.790 15.110 ;
        RECT 0.335 14.270 146.065 14.290 ;
        RECT 0.610 13.450 145.790 14.270 ;
        RECT 0.335 13.430 146.065 13.450 ;
        RECT 0.335 12.610 145.790 13.430 ;
        RECT 0.335 12.590 146.065 12.610 ;
        RECT 0.335 11.770 145.790 12.590 ;
        RECT 0.335 11.750 146.065 11.770 ;
        RECT 0.610 10.930 145.790 11.750 ;
        RECT 0.335 10.910 146.065 10.930 ;
        RECT 0.335 10.090 145.790 10.910 ;
        RECT 0.335 9.230 146.065 10.090 ;
        RECT 0.610 8.410 146.065 9.230 ;
        RECT 0.335 6.710 146.065 8.410 ;
        RECT 0.610 5.890 145.790 6.710 ;
        RECT 0.335 5.030 146.065 5.890 ;
        RECT 0.335 4.210 145.790 5.030 ;
        RECT 0.335 3.350 146.065 4.210 ;
        RECT 0.335 2.530 145.790 3.350 ;
        RECT 0.335 2.510 146.065 2.530 ;
        RECT 0.610 1.690 146.065 2.510 ;
        RECT 0.335 1.670 146.065 1.690 ;
        RECT 0.335 0.850 145.790 1.670 ;
        RECT 0.335 0.315 146.065 0.850 ;
      LAYER Metal4 ;
        RECT 0.380 0.275 15.170 215.185 ;
        RECT 17.790 0.275 21.370 215.185 ;
        RECT 23.990 0.275 90.770 215.185 ;
        RECT 93.390 0.275 96.970 215.185 ;
        RECT 99.590 0.275 146.020 215.185 ;
      LAYER TopMetal1 ;
        RECT 23.660 60.100 130.420 207.660 ;
  END
END RAM_IO_W
END LIBRARY

